# Generated by FakeRAM 2.0
VERSION 5.7 ;
BUSBITCHARS "[]" ;
PROPERTYDEFINITIONS
  MACRO width INTEGER ;
  MACRO depth INTEGER ;
  MACRO banks INTEGER ;
END PROPERTYDEFINITIONS
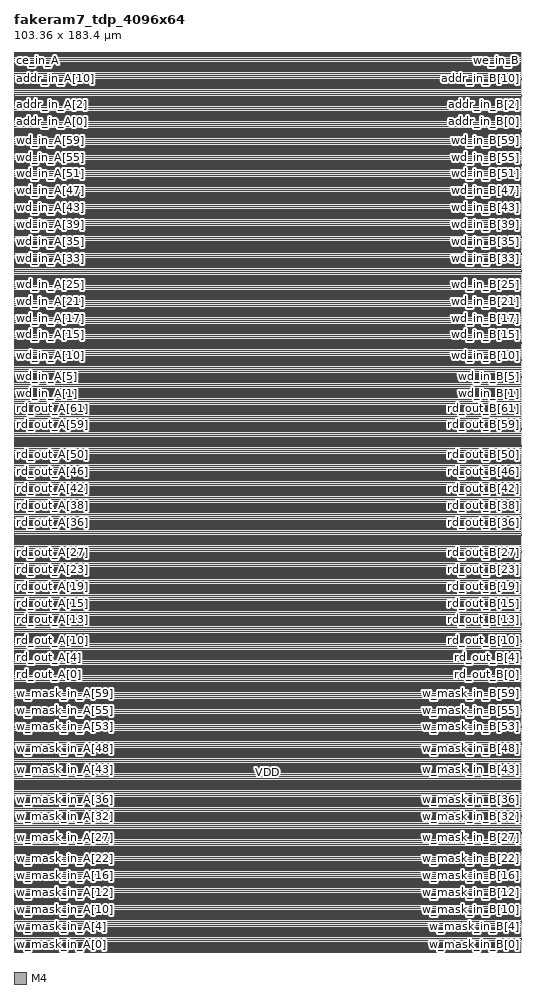
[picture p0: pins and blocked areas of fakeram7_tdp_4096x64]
MACRO fakeram7_tdp_4096x64
  PROPERTY width 64 ;
  PROPERTY depth 4096 ;
  PROPERTY banks 8 ;
  FOREIGN fakeram7_tdp_4096x64 0 0 ;
  SYMMETRY X Y ;
  SIZE 103.360 BY 183.400 ;
  CLASS BLOCK ;
  PIN w_mask_in_A[0]
    DIRECTION INPUT ;
    USE SIGNAL ;
    SHAPE ABUTMENT ;
    PORT
      LAYER M4 ;
      RECT 0.000 0.048 0.024 0.072 ;
    END
  END w_mask_in_A[0]
  PIN w_mask_in_B[0]
    DIRECTION INPUT ;
    USE SIGNAL ;
    SHAPE ABUTMENT ;
    PORT
      LAYER M4 ;
      RECT 103.336 0.048 103.360 0.072 ;
    END
  END w_mask_in_B[0]
  PIN w_mask_in_A[1]
    DIRECTION INPUT ;
    USE SIGNAL ;
    SHAPE ABUTMENT ;
    PORT
      LAYER M4 ;
      RECT 0.000 0.912 0.024 0.936 ;
    END
  END w_mask_in_A[1]
  PIN w_mask_in_B[1]
    DIRECTION INPUT ;
    USE SIGNAL ;
    SHAPE ABUTMENT ;
    PORT
      LAYER M4 ;
      RECT 103.336 0.912 103.360 0.936 ;
    END
  END w_mask_in_B[1]
  PIN w_mask_in_A[2]
    DIRECTION INPUT ;
    USE SIGNAL ;
    SHAPE ABUTMENT ;
    PORT
      LAYER M4 ;
      RECT 0.000 1.776 0.024 1.800 ;
    END
  END w_mask_in_A[2]
  PIN w_mask_in_B[2]
    DIRECTION INPUT ;
    USE SIGNAL ;
    SHAPE ABUTMENT ;
    PORT
      LAYER M4 ;
      RECT 103.336 1.776 103.360 1.800 ;
    END
  END w_mask_in_B[2]
  PIN w_mask_in_A[3]
    DIRECTION INPUT ;
    USE SIGNAL ;
    SHAPE ABUTMENT ;
    PORT
      LAYER M4 ;
      RECT 0.000 2.640 0.024 2.664 ;
    END
  END w_mask_in_A[3]
  PIN w_mask_in_B[3]
    DIRECTION INPUT ;
    USE SIGNAL ;
    SHAPE ABUTMENT ;
    PORT
      LAYER M4 ;
      RECT 103.336 2.640 103.360 2.664 ;
    END
  END w_mask_in_B[3]
  PIN w_mask_in_A[4]
    DIRECTION INPUT ;
    USE SIGNAL ;
    SHAPE ABUTMENT ;
    PORT
      LAYER M4 ;
      RECT 0.000 3.504 0.024 3.528 ;
    END
  END w_mask_in_A[4]
  PIN w_mask_in_B[4]
    DIRECTION INPUT ;
    USE SIGNAL ;
    SHAPE ABUTMENT ;
    PORT
      LAYER M4 ;
      RECT 103.336 3.504 103.360 3.528 ;
    END
  END w_mask_in_B[4]
  PIN w_mask_in_A[5]
    DIRECTION INPUT ;
    USE SIGNAL ;
    SHAPE ABUTMENT ;
    PORT
      LAYER M4 ;
      RECT 0.000 4.368 0.024 4.392 ;
    END
  END w_mask_in_A[5]
  PIN w_mask_in_B[5]
    DIRECTION INPUT ;
    USE SIGNAL ;
    SHAPE ABUTMENT ;
    PORT
      LAYER M4 ;
      RECT 103.336 4.368 103.360 4.392 ;
    END
  END w_mask_in_B[5]
  PIN w_mask_in_A[6]
    DIRECTION INPUT ;
    USE SIGNAL ;
    SHAPE ABUTMENT ;
    PORT
      LAYER M4 ;
      RECT 0.000 5.232 0.024 5.256 ;
    END
  END w_mask_in_A[6]
  PIN w_mask_in_B[6]
    DIRECTION INPUT ;
    USE SIGNAL ;
    SHAPE ABUTMENT ;
    PORT
      LAYER M4 ;
      RECT 103.336 5.232 103.360 5.256 ;
    END
  END w_mask_in_B[6]
  PIN w_mask_in_A[7]
    DIRECTION INPUT ;
    USE SIGNAL ;
    SHAPE ABUTMENT ;
    PORT
      LAYER M4 ;
      RECT 0.000 6.096 0.024 6.120 ;
    END
  END w_mask_in_A[7]
  PIN w_mask_in_B[7]
    DIRECTION INPUT ;
    USE SIGNAL ;
    SHAPE ABUTMENT ;
    PORT
      LAYER M4 ;
      RECT 103.336 6.096 103.360 6.120 ;
    END
  END w_mask_in_B[7]
  PIN w_mask_in_A[8]
    DIRECTION INPUT ;
    USE SIGNAL ;
    SHAPE ABUTMENT ;
    PORT
      LAYER M4 ;
      RECT 0.000 6.960 0.024 6.984 ;
    END
  END w_mask_in_A[8]
  PIN w_mask_in_B[8]
    DIRECTION INPUT ;
    USE SIGNAL ;
    SHAPE ABUTMENT ;
    PORT
      LAYER M4 ;
      RECT 103.336 6.960 103.360 6.984 ;
    END
  END w_mask_in_B[8]
  PIN w_mask_in_A[9]
    DIRECTION INPUT ;
    USE SIGNAL ;
    SHAPE ABUTMENT ;
    PORT
      LAYER M4 ;
      RECT 0.000 7.824 0.024 7.848 ;
    END
  END w_mask_in_A[9]
  PIN w_mask_in_B[9]
    DIRECTION INPUT ;
    USE SIGNAL ;
    SHAPE ABUTMENT ;
    PORT
      LAYER M4 ;
      RECT 103.336 7.824 103.360 7.848 ;
    END
  END w_mask_in_B[9]
  PIN w_mask_in_A[10]
    DIRECTION INPUT ;
    USE SIGNAL ;
    SHAPE ABUTMENT ;
    PORT
      LAYER M4 ;
      RECT 0.000 8.688 0.024 8.712 ;
    END
  END w_mask_in_A[10]
  PIN w_mask_in_B[10]
    DIRECTION INPUT ;
    USE SIGNAL ;
    SHAPE ABUTMENT ;
    PORT
      LAYER M4 ;
      RECT 103.336 8.688 103.360 8.712 ;
    END
  END w_mask_in_B[10]
  PIN w_mask_in_A[11]
    DIRECTION INPUT ;
    USE SIGNAL ;
    SHAPE ABUTMENT ;
    PORT
      LAYER M4 ;
      RECT 0.000 9.552 0.024 9.576 ;
    END
  END w_mask_in_A[11]
  PIN w_mask_in_B[11]
    DIRECTION INPUT ;
    USE SIGNAL ;
    SHAPE ABUTMENT ;
    PORT
      LAYER M4 ;
      RECT 103.336 9.552 103.360 9.576 ;
    END
  END w_mask_in_B[11]
  PIN w_mask_in_A[12]
    DIRECTION INPUT ;
    USE SIGNAL ;
    SHAPE ABUTMENT ;
    PORT
      LAYER M4 ;
      RECT 0.000 10.416 0.024 10.440 ;
    END
  END w_mask_in_A[12]
  PIN w_mask_in_B[12]
    DIRECTION INPUT ;
    USE SIGNAL ;
    SHAPE ABUTMENT ;
    PORT
      LAYER M4 ;
      RECT 103.336 10.416 103.360 10.440 ;
    END
  END w_mask_in_B[12]
  PIN w_mask_in_A[13]
    DIRECTION INPUT ;
    USE SIGNAL ;
    SHAPE ABUTMENT ;
    PORT
      LAYER M4 ;
      RECT 0.000 11.280 0.024 11.304 ;
    END
  END w_mask_in_A[13]
  PIN w_mask_in_B[13]
    DIRECTION INPUT ;
    USE SIGNAL ;
    SHAPE ABUTMENT ;
    PORT
      LAYER M4 ;
      RECT 103.336 11.280 103.360 11.304 ;
    END
  END w_mask_in_B[13]
  PIN w_mask_in_A[14]
    DIRECTION INPUT ;
    USE SIGNAL ;
    SHAPE ABUTMENT ;
    PORT
      LAYER M4 ;
      RECT 0.000 12.144 0.024 12.168 ;
    END
  END w_mask_in_A[14]
  PIN w_mask_in_B[14]
    DIRECTION INPUT ;
    USE SIGNAL ;
    SHAPE ABUTMENT ;
    PORT
      LAYER M4 ;
      RECT 103.336 12.144 103.360 12.168 ;
    END
  END w_mask_in_B[14]
  PIN w_mask_in_A[15]
    DIRECTION INPUT ;
    USE SIGNAL ;
    SHAPE ABUTMENT ;
    PORT
      LAYER M4 ;
      RECT 0.000 13.008 0.024 13.032 ;
    END
  END w_mask_in_A[15]
  PIN w_mask_in_B[15]
    DIRECTION INPUT ;
    USE SIGNAL ;
    SHAPE ABUTMENT ;
    PORT
      LAYER M4 ;
      RECT 103.336 13.008 103.360 13.032 ;
    END
  END w_mask_in_B[15]
  PIN w_mask_in_A[16]
    DIRECTION INPUT ;
    USE SIGNAL ;
    SHAPE ABUTMENT ;
    PORT
      LAYER M4 ;
      RECT 0.000 13.872 0.024 13.896 ;
    END
  END w_mask_in_A[16]
  PIN w_mask_in_B[16]
    DIRECTION INPUT ;
    USE SIGNAL ;
    SHAPE ABUTMENT ;
    PORT
      LAYER M4 ;
      RECT 103.336 13.872 103.360 13.896 ;
    END
  END w_mask_in_B[16]
  PIN w_mask_in_A[17]
    DIRECTION INPUT ;
    USE SIGNAL ;
    SHAPE ABUTMENT ;
    PORT
      LAYER M4 ;
      RECT 0.000 14.736 0.024 14.760 ;
    END
  END w_mask_in_A[17]
  PIN w_mask_in_B[17]
    DIRECTION INPUT ;
    USE SIGNAL ;
    SHAPE ABUTMENT ;
    PORT
      LAYER M4 ;
      RECT 103.336 14.736 103.360 14.760 ;
    END
  END w_mask_in_B[17]
  PIN w_mask_in_A[18]
    DIRECTION INPUT ;
    USE SIGNAL ;
    SHAPE ABUTMENT ;
    PORT
      LAYER M4 ;
      RECT 0.000 15.600 0.024 15.624 ;
    END
  END w_mask_in_A[18]
  PIN w_mask_in_B[18]
    DIRECTION INPUT ;
    USE SIGNAL ;
    SHAPE ABUTMENT ;
    PORT
      LAYER M4 ;
      RECT 103.336 15.600 103.360 15.624 ;
    END
  END w_mask_in_B[18]
  PIN w_mask_in_A[19]
    DIRECTION INPUT ;
    USE SIGNAL ;
    SHAPE ABUTMENT ;
    PORT
      LAYER M4 ;
      RECT 0.000 16.464 0.024 16.488 ;
    END
  END w_mask_in_A[19]
  PIN w_mask_in_B[19]
    DIRECTION INPUT ;
    USE SIGNAL ;
    SHAPE ABUTMENT ;
    PORT
      LAYER M4 ;
      RECT 103.336 16.464 103.360 16.488 ;
    END
  END w_mask_in_B[19]
  PIN w_mask_in_A[20]
    DIRECTION INPUT ;
    USE SIGNAL ;
    SHAPE ABUTMENT ;
    PORT
      LAYER M4 ;
      RECT 0.000 17.328 0.024 17.352 ;
    END
  END w_mask_in_A[20]
  PIN w_mask_in_B[20]
    DIRECTION INPUT ;
    USE SIGNAL ;
    SHAPE ABUTMENT ;
    PORT
      LAYER M4 ;
      RECT 103.336 17.328 103.360 17.352 ;
    END
  END w_mask_in_B[20]
  PIN w_mask_in_A[21]
    DIRECTION INPUT ;
    USE SIGNAL ;
    SHAPE ABUTMENT ;
    PORT
      LAYER M4 ;
      RECT 0.000 18.192 0.024 18.216 ;
    END
  END w_mask_in_A[21]
  PIN w_mask_in_B[21]
    DIRECTION INPUT ;
    USE SIGNAL ;
    SHAPE ABUTMENT ;
    PORT
      LAYER M4 ;
      RECT 103.336 18.192 103.360 18.216 ;
    END
  END w_mask_in_B[21]
  PIN w_mask_in_A[22]
    DIRECTION INPUT ;
    USE SIGNAL ;
    SHAPE ABUTMENT ;
    PORT
      LAYER M4 ;
      RECT 0.000 19.056 0.024 19.080 ;
    END
  END w_mask_in_A[22]
  PIN w_mask_in_B[22]
    DIRECTION INPUT ;
    USE SIGNAL ;
    SHAPE ABUTMENT ;
    PORT
      LAYER M4 ;
      RECT 103.336 19.056 103.360 19.080 ;
    END
  END w_mask_in_B[22]
  PIN w_mask_in_A[23]
    DIRECTION INPUT ;
    USE SIGNAL ;
    SHAPE ABUTMENT ;
    PORT
      LAYER M4 ;
      RECT 0.000 19.920 0.024 19.944 ;
    END
  END w_mask_in_A[23]
  PIN w_mask_in_B[23]
    DIRECTION INPUT ;
    USE SIGNAL ;
    SHAPE ABUTMENT ;
    PORT
      LAYER M4 ;
      RECT 103.336 19.920 103.360 19.944 ;
    END
  END w_mask_in_B[23]
  PIN w_mask_in_A[24]
    DIRECTION INPUT ;
    USE SIGNAL ;
    SHAPE ABUTMENT ;
    PORT
      LAYER M4 ;
      RECT 0.000 20.784 0.024 20.808 ;
    END
  END w_mask_in_A[24]
  PIN w_mask_in_B[24]
    DIRECTION INPUT ;
    USE SIGNAL ;
    SHAPE ABUTMENT ;
    PORT
      LAYER M4 ;
      RECT 103.336 20.784 103.360 20.808 ;
    END
  END w_mask_in_B[24]
  PIN w_mask_in_A[25]
    DIRECTION INPUT ;
    USE SIGNAL ;
    SHAPE ABUTMENT ;
    PORT
      LAYER M4 ;
      RECT 0.000 21.648 0.024 21.672 ;
    END
  END w_mask_in_A[25]
  PIN w_mask_in_B[25]
    DIRECTION INPUT ;
    USE SIGNAL ;
    SHAPE ABUTMENT ;
    PORT
      LAYER M4 ;
      RECT 103.336 21.648 103.360 21.672 ;
    END
  END w_mask_in_B[25]
  PIN w_mask_in_A[26]
    DIRECTION INPUT ;
    USE SIGNAL ;
    SHAPE ABUTMENT ;
    PORT
      LAYER M4 ;
      RECT 0.000 22.512 0.024 22.536 ;
    END
  END w_mask_in_A[26]
  PIN w_mask_in_B[26]
    DIRECTION INPUT ;
    USE SIGNAL ;
    SHAPE ABUTMENT ;
    PORT
      LAYER M4 ;
      RECT 103.336 22.512 103.360 22.536 ;
    END
  END w_mask_in_B[26]
  PIN w_mask_in_A[27]
    DIRECTION INPUT ;
    USE SIGNAL ;
    SHAPE ABUTMENT ;
    PORT
      LAYER M4 ;
      RECT 0.000 23.376 0.024 23.400 ;
    END
  END w_mask_in_A[27]
  PIN w_mask_in_B[27]
    DIRECTION INPUT ;
    USE SIGNAL ;
    SHAPE ABUTMENT ;
    PORT
      LAYER M4 ;
      RECT 103.336 23.376 103.360 23.400 ;
    END
  END w_mask_in_B[27]
  PIN w_mask_in_A[28]
    DIRECTION INPUT ;
    USE SIGNAL ;
    SHAPE ABUTMENT ;
    PORT
      LAYER M4 ;
      RECT 0.000 24.240 0.024 24.264 ;
    END
  END w_mask_in_A[28]
  PIN w_mask_in_B[28]
    DIRECTION INPUT ;
    USE SIGNAL ;
    SHAPE ABUTMENT ;
    PORT
      LAYER M4 ;
      RECT 103.336 24.240 103.360 24.264 ;
    END
  END w_mask_in_B[28]
  PIN w_mask_in_A[29]
    DIRECTION INPUT ;
    USE SIGNAL ;
    SHAPE ABUTMENT ;
    PORT
      LAYER M4 ;
      RECT 0.000 25.104 0.024 25.128 ;
    END
  END w_mask_in_A[29]
  PIN w_mask_in_B[29]
    DIRECTION INPUT ;
    USE SIGNAL ;
    SHAPE ABUTMENT ;
    PORT
      LAYER M4 ;
      RECT 103.336 25.104 103.360 25.128 ;
    END
  END w_mask_in_B[29]
  PIN w_mask_in_A[30]
    DIRECTION INPUT ;
    USE SIGNAL ;
    SHAPE ABUTMENT ;
    PORT
      LAYER M4 ;
      RECT 0.000 25.968 0.024 25.992 ;
    END
  END w_mask_in_A[30]
  PIN w_mask_in_B[30]
    DIRECTION INPUT ;
    USE SIGNAL ;
    SHAPE ABUTMENT ;
    PORT
      LAYER M4 ;
      RECT 103.336 25.968 103.360 25.992 ;
    END
  END w_mask_in_B[30]
  PIN w_mask_in_A[31]
    DIRECTION INPUT ;
    USE SIGNAL ;
    SHAPE ABUTMENT ;
    PORT
      LAYER M4 ;
      RECT 0.000 26.832 0.024 26.856 ;
    END
  END w_mask_in_A[31]
  PIN w_mask_in_B[31]
    DIRECTION INPUT ;
    USE SIGNAL ;
    SHAPE ABUTMENT ;
    PORT
      LAYER M4 ;
      RECT 103.336 26.832 103.360 26.856 ;
    END
  END w_mask_in_B[31]
  PIN w_mask_in_A[32]
    DIRECTION INPUT ;
    USE SIGNAL ;
    SHAPE ABUTMENT ;
    PORT
      LAYER M4 ;
      RECT 0.000 27.696 0.024 27.720 ;
    END
  END w_mask_in_A[32]
  PIN w_mask_in_B[32]
    DIRECTION INPUT ;
    USE SIGNAL ;
    SHAPE ABUTMENT ;
    PORT
      LAYER M4 ;
      RECT 103.336 27.696 103.360 27.720 ;
    END
  END w_mask_in_B[32]
  PIN w_mask_in_A[33]
    DIRECTION INPUT ;
    USE SIGNAL ;
    SHAPE ABUTMENT ;
    PORT
      LAYER M4 ;
      RECT 0.000 28.560 0.024 28.584 ;
    END
  END w_mask_in_A[33]
  PIN w_mask_in_B[33]
    DIRECTION INPUT ;
    USE SIGNAL ;
    SHAPE ABUTMENT ;
    PORT
      LAYER M4 ;
      RECT 103.336 28.560 103.360 28.584 ;
    END
  END w_mask_in_B[33]
  PIN w_mask_in_A[34]
    DIRECTION INPUT ;
    USE SIGNAL ;
    SHAPE ABUTMENT ;
    PORT
      LAYER M4 ;
      RECT 0.000 29.424 0.024 29.448 ;
    END
  END w_mask_in_A[34]
  PIN w_mask_in_B[34]
    DIRECTION INPUT ;
    USE SIGNAL ;
    SHAPE ABUTMENT ;
    PORT
      LAYER M4 ;
      RECT 103.336 29.424 103.360 29.448 ;
    END
  END w_mask_in_B[34]
  PIN w_mask_in_A[35]
    DIRECTION INPUT ;
    USE SIGNAL ;
    SHAPE ABUTMENT ;
    PORT
      LAYER M4 ;
      RECT 0.000 30.288 0.024 30.312 ;
    END
  END w_mask_in_A[35]
  PIN w_mask_in_B[35]
    DIRECTION INPUT ;
    USE SIGNAL ;
    SHAPE ABUTMENT ;
    PORT
      LAYER M4 ;
      RECT 103.336 30.288 103.360 30.312 ;
    END
  END w_mask_in_B[35]
  PIN w_mask_in_A[36]
    DIRECTION INPUT ;
    USE SIGNAL ;
    SHAPE ABUTMENT ;
    PORT
      LAYER M4 ;
      RECT 0.000 31.152 0.024 31.176 ;
    END
  END w_mask_in_A[36]
  PIN w_mask_in_B[36]
    DIRECTION INPUT ;
    USE SIGNAL ;
    SHAPE ABUTMENT ;
    PORT
      LAYER M4 ;
      RECT 103.336 31.152 103.360 31.176 ;
    END
  END w_mask_in_B[36]
  PIN w_mask_in_A[37]
    DIRECTION INPUT ;
    USE SIGNAL ;
    SHAPE ABUTMENT ;
    PORT
      LAYER M4 ;
      RECT 0.000 32.016 0.024 32.040 ;
    END
  END w_mask_in_A[37]
  PIN w_mask_in_B[37]
    DIRECTION INPUT ;
    USE SIGNAL ;
    SHAPE ABUTMENT ;
    PORT
      LAYER M4 ;
      RECT 103.336 32.016 103.360 32.040 ;
    END
  END w_mask_in_B[37]
  PIN w_mask_in_A[38]
    DIRECTION INPUT ;
    USE SIGNAL ;
    SHAPE ABUTMENT ;
    PORT
      LAYER M4 ;
      RECT 0.000 32.880 0.024 32.904 ;
    END
  END w_mask_in_A[38]
  PIN w_mask_in_B[38]
    DIRECTION INPUT ;
    USE SIGNAL ;
    SHAPE ABUTMENT ;
    PORT
      LAYER M4 ;
      RECT 103.336 32.880 103.360 32.904 ;
    END
  END w_mask_in_B[38]
  PIN w_mask_in_A[39]
    DIRECTION INPUT ;
    USE SIGNAL ;
    SHAPE ABUTMENT ;
    PORT
      LAYER M4 ;
      RECT 0.000 33.744 0.024 33.768 ;
    END
  END w_mask_in_A[39]
  PIN w_mask_in_B[39]
    DIRECTION INPUT ;
    USE SIGNAL ;
    SHAPE ABUTMENT ;
    PORT
      LAYER M4 ;
      RECT 103.336 33.744 103.360 33.768 ;
    END
  END w_mask_in_B[39]
  PIN w_mask_in_A[40]
    DIRECTION INPUT ;
    USE SIGNAL ;
    SHAPE ABUTMENT ;
    PORT
      LAYER M4 ;
      RECT 0.000 34.608 0.024 34.632 ;
    END
  END w_mask_in_A[40]
  PIN w_mask_in_B[40]
    DIRECTION INPUT ;
    USE SIGNAL ;
    SHAPE ABUTMENT ;
    PORT
      LAYER M4 ;
      RECT 103.336 34.608 103.360 34.632 ;
    END
  END w_mask_in_B[40]
  PIN w_mask_in_A[41]
    DIRECTION INPUT ;
    USE SIGNAL ;
    SHAPE ABUTMENT ;
    PORT
      LAYER M4 ;
      RECT 0.000 35.472 0.024 35.496 ;
    END
  END w_mask_in_A[41]
  PIN w_mask_in_B[41]
    DIRECTION INPUT ;
    USE SIGNAL ;
    SHAPE ABUTMENT ;
    PORT
      LAYER M4 ;
      RECT 103.336 35.472 103.360 35.496 ;
    END
  END w_mask_in_B[41]
  PIN w_mask_in_A[42]
    DIRECTION INPUT ;
    USE SIGNAL ;
    SHAPE ABUTMENT ;
    PORT
      LAYER M4 ;
      RECT 0.000 36.336 0.024 36.360 ;
    END
  END w_mask_in_A[42]
  PIN w_mask_in_B[42]
    DIRECTION INPUT ;
    USE SIGNAL ;
    SHAPE ABUTMENT ;
    PORT
      LAYER M4 ;
      RECT 103.336 36.336 103.360 36.360 ;
    END
  END w_mask_in_B[42]
  PIN w_mask_in_A[43]
    DIRECTION INPUT ;
    USE SIGNAL ;
    SHAPE ABUTMENT ;
    PORT
      LAYER M4 ;
      RECT 0.000 37.200 0.024 37.224 ;
    END
  END w_mask_in_A[43]
  PIN w_mask_in_B[43]
    DIRECTION INPUT ;
    USE SIGNAL ;
    SHAPE ABUTMENT ;
    PORT
      LAYER M4 ;
      RECT 103.336 37.200 103.360 37.224 ;
    END
  END w_mask_in_B[43]
  PIN w_mask_in_A[44]
    DIRECTION INPUT ;
    USE SIGNAL ;
    SHAPE ABUTMENT ;
    PORT
      LAYER M4 ;
      RECT 0.000 38.064 0.024 38.088 ;
    END
  END w_mask_in_A[44]
  PIN w_mask_in_B[44]
    DIRECTION INPUT ;
    USE SIGNAL ;
    SHAPE ABUTMENT ;
    PORT
      LAYER M4 ;
      RECT 103.336 38.064 103.360 38.088 ;
    END
  END w_mask_in_B[44]
  PIN w_mask_in_A[45]
    DIRECTION INPUT ;
    USE SIGNAL ;
    SHAPE ABUTMENT ;
    PORT
      LAYER M4 ;
      RECT 0.000 38.928 0.024 38.952 ;
    END
  END w_mask_in_A[45]
  PIN w_mask_in_B[45]
    DIRECTION INPUT ;
    USE SIGNAL ;
    SHAPE ABUTMENT ;
    PORT
      LAYER M4 ;
      RECT 103.336 38.928 103.360 38.952 ;
    END
  END w_mask_in_B[45]
  PIN w_mask_in_A[46]
    DIRECTION INPUT ;
    USE SIGNAL ;
    SHAPE ABUTMENT ;
    PORT
      LAYER M4 ;
      RECT 0.000 39.792 0.024 39.816 ;
    END
  END w_mask_in_A[46]
  PIN w_mask_in_B[46]
    DIRECTION INPUT ;
    USE SIGNAL ;
    SHAPE ABUTMENT ;
    PORT
      LAYER M4 ;
      RECT 103.336 39.792 103.360 39.816 ;
    END
  END w_mask_in_B[46]
  PIN w_mask_in_A[47]
    DIRECTION INPUT ;
    USE SIGNAL ;
    SHAPE ABUTMENT ;
    PORT
      LAYER M4 ;
      RECT 0.000 40.656 0.024 40.680 ;
    END
  END w_mask_in_A[47]
  PIN w_mask_in_B[47]
    DIRECTION INPUT ;
    USE SIGNAL ;
    SHAPE ABUTMENT ;
    PORT
      LAYER M4 ;
      RECT 103.336 40.656 103.360 40.680 ;
    END
  END w_mask_in_B[47]
  PIN w_mask_in_A[48]
    DIRECTION INPUT ;
    USE SIGNAL ;
    SHAPE ABUTMENT ;
    PORT
      LAYER M4 ;
      RECT 0.000 41.520 0.024 41.544 ;
    END
  END w_mask_in_A[48]
  PIN w_mask_in_B[48]
    DIRECTION INPUT ;
    USE SIGNAL ;
    SHAPE ABUTMENT ;
    PORT
      LAYER M4 ;
      RECT 103.336 41.520 103.360 41.544 ;
    END
  END w_mask_in_B[48]
  PIN w_mask_in_A[49]
    DIRECTION INPUT ;
    USE SIGNAL ;
    SHAPE ABUTMENT ;
    PORT
      LAYER M4 ;
      RECT 0.000 42.384 0.024 42.408 ;
    END
  END w_mask_in_A[49]
  PIN w_mask_in_B[49]
    DIRECTION INPUT ;
    USE SIGNAL ;
    SHAPE ABUTMENT ;
    PORT
      LAYER M4 ;
      RECT 103.336 42.384 103.360 42.408 ;
    END
  END w_mask_in_B[49]
  PIN w_mask_in_A[50]
    DIRECTION INPUT ;
    USE SIGNAL ;
    SHAPE ABUTMENT ;
    PORT
      LAYER M4 ;
      RECT 0.000 43.248 0.024 43.272 ;
    END
  END w_mask_in_A[50]
  PIN w_mask_in_B[50]
    DIRECTION INPUT ;
    USE SIGNAL ;
    SHAPE ABUTMENT ;
    PORT
      LAYER M4 ;
      RECT 103.336 43.248 103.360 43.272 ;
    END
  END w_mask_in_B[50]
  PIN w_mask_in_A[51]
    DIRECTION INPUT ;
    USE SIGNAL ;
    SHAPE ABUTMENT ;
    PORT
      LAYER M4 ;
      RECT 0.000 44.112 0.024 44.136 ;
    END
  END w_mask_in_A[51]
  PIN w_mask_in_B[51]
    DIRECTION INPUT ;
    USE SIGNAL ;
    SHAPE ABUTMENT ;
    PORT
      LAYER M4 ;
      RECT 103.336 44.112 103.360 44.136 ;
    END
  END w_mask_in_B[51]
  PIN w_mask_in_A[52]
    DIRECTION INPUT ;
    USE SIGNAL ;
    SHAPE ABUTMENT ;
    PORT
      LAYER M4 ;
      RECT 0.000 44.976 0.024 45.000 ;
    END
  END w_mask_in_A[52]
  PIN w_mask_in_B[52]
    DIRECTION INPUT ;
    USE SIGNAL ;
    SHAPE ABUTMENT ;
    PORT
      LAYER M4 ;
      RECT 103.336 44.976 103.360 45.000 ;
    END
  END w_mask_in_B[52]
  PIN w_mask_in_A[53]
    DIRECTION INPUT ;
    USE SIGNAL ;
    SHAPE ABUTMENT ;
    PORT
      LAYER M4 ;
      RECT 0.000 45.840 0.024 45.864 ;
    END
  END w_mask_in_A[53]
  PIN w_mask_in_B[53]
    DIRECTION INPUT ;
    USE SIGNAL ;
    SHAPE ABUTMENT ;
    PORT
      LAYER M4 ;
      RECT 103.336 45.840 103.360 45.864 ;
    END
  END w_mask_in_B[53]
  PIN w_mask_in_A[54]
    DIRECTION INPUT ;
    USE SIGNAL ;
    SHAPE ABUTMENT ;
    PORT
      LAYER M4 ;
      RECT 0.000 46.704 0.024 46.728 ;
    END
  END w_mask_in_A[54]
  PIN w_mask_in_B[54]
    DIRECTION INPUT ;
    USE SIGNAL ;
    SHAPE ABUTMENT ;
    PORT
      LAYER M4 ;
      RECT 103.336 46.704 103.360 46.728 ;
    END
  END w_mask_in_B[54]
  PIN w_mask_in_A[55]
    DIRECTION INPUT ;
    USE SIGNAL ;
    SHAPE ABUTMENT ;
    PORT
      LAYER M4 ;
      RECT 0.000 47.568 0.024 47.592 ;
    END
  END w_mask_in_A[55]
  PIN w_mask_in_B[55]
    DIRECTION INPUT ;
    USE SIGNAL ;
    SHAPE ABUTMENT ;
    PORT
      LAYER M4 ;
      RECT 103.336 47.568 103.360 47.592 ;
    END
  END w_mask_in_B[55]
  PIN w_mask_in_A[56]
    DIRECTION INPUT ;
    USE SIGNAL ;
    SHAPE ABUTMENT ;
    PORT
      LAYER M4 ;
      RECT 0.000 48.432 0.024 48.456 ;
    END
  END w_mask_in_A[56]
  PIN w_mask_in_B[56]
    DIRECTION INPUT ;
    USE SIGNAL ;
    SHAPE ABUTMENT ;
    PORT
      LAYER M4 ;
      RECT 103.336 48.432 103.360 48.456 ;
    END
  END w_mask_in_B[56]
  PIN w_mask_in_A[57]
    DIRECTION INPUT ;
    USE SIGNAL ;
    SHAPE ABUTMENT ;
    PORT
      LAYER M4 ;
      RECT 0.000 49.296 0.024 49.320 ;
    END
  END w_mask_in_A[57]
  PIN w_mask_in_B[57]
    DIRECTION INPUT ;
    USE SIGNAL ;
    SHAPE ABUTMENT ;
    PORT
      LAYER M4 ;
      RECT 103.336 49.296 103.360 49.320 ;
    END
  END w_mask_in_B[57]
  PIN w_mask_in_A[58]
    DIRECTION INPUT ;
    USE SIGNAL ;
    SHAPE ABUTMENT ;
    PORT
      LAYER M4 ;
      RECT 0.000 50.160 0.024 50.184 ;
    END
  END w_mask_in_A[58]
  PIN w_mask_in_B[58]
    DIRECTION INPUT ;
    USE SIGNAL ;
    SHAPE ABUTMENT ;
    PORT
      LAYER M4 ;
      RECT 103.336 50.160 103.360 50.184 ;
    END
  END w_mask_in_B[58]
  PIN w_mask_in_A[59]
    DIRECTION INPUT ;
    USE SIGNAL ;
    SHAPE ABUTMENT ;
    PORT
      LAYER M4 ;
      RECT 0.000 51.024 0.024 51.048 ;
    END
  END w_mask_in_A[59]
  PIN w_mask_in_B[59]
    DIRECTION INPUT ;
    USE SIGNAL ;
    SHAPE ABUTMENT ;
    PORT
      LAYER M4 ;
      RECT 103.336 51.024 103.360 51.048 ;
    END
  END w_mask_in_B[59]
  PIN w_mask_in_A[60]
    DIRECTION INPUT ;
    USE SIGNAL ;
    SHAPE ABUTMENT ;
    PORT
      LAYER M4 ;
      RECT 0.000 51.888 0.024 51.912 ;
    END
  END w_mask_in_A[60]
  PIN w_mask_in_B[60]
    DIRECTION INPUT ;
    USE SIGNAL ;
    SHAPE ABUTMENT ;
    PORT
      LAYER M4 ;
      RECT 103.336 51.888 103.360 51.912 ;
    END
  END w_mask_in_B[60]
  PIN w_mask_in_A[61]
    DIRECTION INPUT ;
    USE SIGNAL ;
    SHAPE ABUTMENT ;
    PORT
      LAYER M4 ;
      RECT 0.000 52.752 0.024 52.776 ;
    END
  END w_mask_in_A[61]
  PIN w_mask_in_B[61]
    DIRECTION INPUT ;
    USE SIGNAL ;
    SHAPE ABUTMENT ;
    PORT
      LAYER M4 ;
      RECT 103.336 52.752 103.360 52.776 ;
    END
  END w_mask_in_B[61]
  PIN w_mask_in_A[62]
    DIRECTION INPUT ;
    USE SIGNAL ;
    SHAPE ABUTMENT ;
    PORT
      LAYER M4 ;
      RECT 0.000 53.616 0.024 53.640 ;
    END
  END w_mask_in_A[62]
  PIN w_mask_in_B[62]
    DIRECTION INPUT ;
    USE SIGNAL ;
    SHAPE ABUTMENT ;
    PORT
      LAYER M4 ;
      RECT 103.336 53.616 103.360 53.640 ;
    END
  END w_mask_in_B[62]
  PIN w_mask_in_A[63]
    DIRECTION INPUT ;
    USE SIGNAL ;
    SHAPE ABUTMENT ;
    PORT
      LAYER M4 ;
      RECT 0.000 54.480 0.024 54.504 ;
    END
  END w_mask_in_A[63]
  PIN w_mask_in_B[63]
    DIRECTION INPUT ;
    USE SIGNAL ;
    SHAPE ABUTMENT ;
    PORT
      LAYER M4 ;
      RECT 103.336 54.480 103.360 54.504 ;
    END
  END w_mask_in_B[63]
  PIN rd_out_A[0]
    DIRECTION OUTPUT ;
    USE SIGNAL ;
    SHAPE ABUTMENT ;
    PORT
      LAYER M4 ;
      RECT 0.000 56.448 0.024 56.472 ;
    END
  END rd_out_A[0]
  PIN rd_out_B[0]
    DIRECTION OUTPUT ;
    USE SIGNAL ;
    SHAPE ABUTMENT ;
    PORT
      LAYER M4 ;
      RECT 103.336 56.448 103.360 56.472 ;
    END
  END rd_out_B[0]
  PIN rd_out_A[1]
    DIRECTION OUTPUT ;
    USE SIGNAL ;
    SHAPE ABUTMENT ;
    PORT
      LAYER M4 ;
      RECT 0.000 57.312 0.024 57.336 ;
    END
  END rd_out_A[1]
  PIN rd_out_B[1]
    DIRECTION OUTPUT ;
    USE SIGNAL ;
    SHAPE ABUTMENT ;
    PORT
      LAYER M4 ;
      RECT 103.336 57.312 103.360 57.336 ;
    END
  END rd_out_B[1]
  PIN rd_out_A[2]
    DIRECTION OUTPUT ;
    USE SIGNAL ;
    SHAPE ABUTMENT ;
    PORT
      LAYER M4 ;
      RECT 0.000 58.176 0.024 58.200 ;
    END
  END rd_out_A[2]
  PIN rd_out_B[2]
    DIRECTION OUTPUT ;
    USE SIGNAL ;
    SHAPE ABUTMENT ;
    PORT
      LAYER M4 ;
      RECT 103.336 58.176 103.360 58.200 ;
    END
  END rd_out_B[2]
  PIN rd_out_A[3]
    DIRECTION OUTPUT ;
    USE SIGNAL ;
    SHAPE ABUTMENT ;
    PORT
      LAYER M4 ;
      RECT 0.000 59.040 0.024 59.064 ;
    END
  END rd_out_A[3]
  PIN rd_out_B[3]
    DIRECTION OUTPUT ;
    USE SIGNAL ;
    SHAPE ABUTMENT ;
    PORT
      LAYER M4 ;
      RECT 103.336 59.040 103.360 59.064 ;
    END
  END rd_out_B[3]
  PIN rd_out_A[4]
    DIRECTION OUTPUT ;
    USE SIGNAL ;
    SHAPE ABUTMENT ;
    PORT
      LAYER M4 ;
      RECT 0.000 59.904 0.024 59.928 ;
    END
  END rd_out_A[4]
  PIN rd_out_B[4]
    DIRECTION OUTPUT ;
    USE SIGNAL ;
    SHAPE ABUTMENT ;
    PORT
      LAYER M4 ;
      RECT 103.336 59.904 103.360 59.928 ;
    END
  END rd_out_B[4]
  PIN rd_out_A[5]
    DIRECTION OUTPUT ;
    USE SIGNAL ;
    SHAPE ABUTMENT ;
    PORT
      LAYER M4 ;
      RECT 0.000 60.768 0.024 60.792 ;
    END
  END rd_out_A[5]
  PIN rd_out_B[5]
    DIRECTION OUTPUT ;
    USE SIGNAL ;
    SHAPE ABUTMENT ;
    PORT
      LAYER M4 ;
      RECT 103.336 60.768 103.360 60.792 ;
    END
  END rd_out_B[5]
  PIN rd_out_A[6]
    DIRECTION OUTPUT ;
    USE SIGNAL ;
    SHAPE ABUTMENT ;
    PORT
      LAYER M4 ;
      RECT 0.000 61.632 0.024 61.656 ;
    END
  END rd_out_A[6]
  PIN rd_out_B[6]
    DIRECTION OUTPUT ;
    USE SIGNAL ;
    SHAPE ABUTMENT ;
    PORT
      LAYER M4 ;
      RECT 103.336 61.632 103.360 61.656 ;
    END
  END rd_out_B[6]
  PIN rd_out_A[7]
    DIRECTION OUTPUT ;
    USE SIGNAL ;
    SHAPE ABUTMENT ;
    PORT
      LAYER M4 ;
      RECT 0.000 62.496 0.024 62.520 ;
    END
  END rd_out_A[7]
  PIN rd_out_B[7]
    DIRECTION OUTPUT ;
    USE SIGNAL ;
    SHAPE ABUTMENT ;
    PORT
      LAYER M4 ;
      RECT 103.336 62.496 103.360 62.520 ;
    END
  END rd_out_B[7]
  PIN rd_out_A[8]
    DIRECTION OUTPUT ;
    USE SIGNAL ;
    SHAPE ABUTMENT ;
    PORT
      LAYER M4 ;
      RECT 0.000 63.360 0.024 63.384 ;
    END
  END rd_out_A[8]
  PIN rd_out_B[8]
    DIRECTION OUTPUT ;
    USE SIGNAL ;
    SHAPE ABUTMENT ;
    PORT
      LAYER M4 ;
      RECT 103.336 63.360 103.360 63.384 ;
    END
  END rd_out_B[8]
  PIN rd_out_A[9]
    DIRECTION OUTPUT ;
    USE SIGNAL ;
    SHAPE ABUTMENT ;
    PORT
      LAYER M4 ;
      RECT 0.000 64.224 0.024 64.248 ;
    END
  END rd_out_A[9]
  PIN rd_out_B[9]
    DIRECTION OUTPUT ;
    USE SIGNAL ;
    SHAPE ABUTMENT ;
    PORT
      LAYER M4 ;
      RECT 103.336 64.224 103.360 64.248 ;
    END
  END rd_out_B[9]
  PIN rd_out_A[10]
    DIRECTION OUTPUT ;
    USE SIGNAL ;
    SHAPE ABUTMENT ;
    PORT
      LAYER M4 ;
      RECT 0.000 65.088 0.024 65.112 ;
    END
  END rd_out_A[10]
  PIN rd_out_B[10]
    DIRECTION OUTPUT ;
    USE SIGNAL ;
    SHAPE ABUTMENT ;
    PORT
      LAYER M4 ;
      RECT 103.336 65.088 103.360 65.112 ;
    END
  END rd_out_B[10]
  PIN rd_out_A[11]
    DIRECTION OUTPUT ;
    USE SIGNAL ;
    SHAPE ABUTMENT ;
    PORT
      LAYER M4 ;
      RECT 0.000 65.952 0.024 65.976 ;
    END
  END rd_out_A[11]
  PIN rd_out_B[11]
    DIRECTION OUTPUT ;
    USE SIGNAL ;
    SHAPE ABUTMENT ;
    PORT
      LAYER M4 ;
      RECT 103.336 65.952 103.360 65.976 ;
    END
  END rd_out_B[11]
  PIN rd_out_A[12]
    DIRECTION OUTPUT ;
    USE SIGNAL ;
    SHAPE ABUTMENT ;
    PORT
      LAYER M4 ;
      RECT 0.000 66.816 0.024 66.840 ;
    END
  END rd_out_A[12]
  PIN rd_out_B[12]
    DIRECTION OUTPUT ;
    USE SIGNAL ;
    SHAPE ABUTMENT ;
    PORT
      LAYER M4 ;
      RECT 103.336 66.816 103.360 66.840 ;
    END
  END rd_out_B[12]
  PIN rd_out_A[13]
    DIRECTION OUTPUT ;
    USE SIGNAL ;
    SHAPE ABUTMENT ;
    PORT
      LAYER M4 ;
      RECT 0.000 67.680 0.024 67.704 ;
    END
  END rd_out_A[13]
  PIN rd_out_B[13]
    DIRECTION OUTPUT ;
    USE SIGNAL ;
    SHAPE ABUTMENT ;
    PORT
      LAYER M4 ;
      RECT 103.336 67.680 103.360 67.704 ;
    END
  END rd_out_B[13]
  PIN rd_out_A[14]
    DIRECTION OUTPUT ;
    USE SIGNAL ;
    SHAPE ABUTMENT ;
    PORT
      LAYER M4 ;
      RECT 0.000 68.544 0.024 68.568 ;
    END
  END rd_out_A[14]
  PIN rd_out_B[14]
    DIRECTION OUTPUT ;
    USE SIGNAL ;
    SHAPE ABUTMENT ;
    PORT
      LAYER M4 ;
      RECT 103.336 68.544 103.360 68.568 ;
    END
  END rd_out_B[14]
  PIN rd_out_A[15]
    DIRECTION OUTPUT ;
    USE SIGNAL ;
    SHAPE ABUTMENT ;
    PORT
      LAYER M4 ;
      RECT 0.000 69.408 0.024 69.432 ;
    END
  END rd_out_A[15]
  PIN rd_out_B[15]
    DIRECTION OUTPUT ;
    USE SIGNAL ;
    SHAPE ABUTMENT ;
    PORT
      LAYER M4 ;
      RECT 103.336 69.408 103.360 69.432 ;
    END
  END rd_out_B[15]
  PIN rd_out_A[16]
    DIRECTION OUTPUT ;
    USE SIGNAL ;
    SHAPE ABUTMENT ;
    PORT
      LAYER M4 ;
      RECT 0.000 70.272 0.024 70.296 ;
    END
  END rd_out_A[16]
  PIN rd_out_B[16]
    DIRECTION OUTPUT ;
    USE SIGNAL ;
    SHAPE ABUTMENT ;
    PORT
      LAYER M4 ;
      RECT 103.336 70.272 103.360 70.296 ;
    END
  END rd_out_B[16]
  PIN rd_out_A[17]
    DIRECTION OUTPUT ;
    USE SIGNAL ;
    SHAPE ABUTMENT ;
    PORT
      LAYER M4 ;
      RECT 0.000 71.136 0.024 71.160 ;
    END
  END rd_out_A[17]
  PIN rd_out_B[17]
    DIRECTION OUTPUT ;
    USE SIGNAL ;
    SHAPE ABUTMENT ;
    PORT
      LAYER M4 ;
      RECT 103.336 71.136 103.360 71.160 ;
    END
  END rd_out_B[17]
  PIN rd_out_A[18]
    DIRECTION OUTPUT ;
    USE SIGNAL ;
    SHAPE ABUTMENT ;
    PORT
      LAYER M4 ;
      RECT 0.000 72.000 0.024 72.024 ;
    END
  END rd_out_A[18]
  PIN rd_out_B[18]
    DIRECTION OUTPUT ;
    USE SIGNAL ;
    SHAPE ABUTMENT ;
    PORT
      LAYER M4 ;
      RECT 103.336 72.000 103.360 72.024 ;
    END
  END rd_out_B[18]
  PIN rd_out_A[19]
    DIRECTION OUTPUT ;
    USE SIGNAL ;
    SHAPE ABUTMENT ;
    PORT
      LAYER M4 ;
      RECT 0.000 72.864 0.024 72.888 ;
    END
  END rd_out_A[19]
  PIN rd_out_B[19]
    DIRECTION OUTPUT ;
    USE SIGNAL ;
    SHAPE ABUTMENT ;
    PORT
      LAYER M4 ;
      RECT 103.336 72.864 103.360 72.888 ;
    END
  END rd_out_B[19]
  PIN rd_out_A[20]
    DIRECTION OUTPUT ;
    USE SIGNAL ;
    SHAPE ABUTMENT ;
    PORT
      LAYER M4 ;
      RECT 0.000 73.728 0.024 73.752 ;
    END
  END rd_out_A[20]
  PIN rd_out_B[20]
    DIRECTION OUTPUT ;
    USE SIGNAL ;
    SHAPE ABUTMENT ;
    PORT
      LAYER M4 ;
      RECT 103.336 73.728 103.360 73.752 ;
    END
  END rd_out_B[20]
  PIN rd_out_A[21]
    DIRECTION OUTPUT ;
    USE SIGNAL ;
    SHAPE ABUTMENT ;
    PORT
      LAYER M4 ;
      RECT 0.000 74.592 0.024 74.616 ;
    END
  END rd_out_A[21]
  PIN rd_out_B[21]
    DIRECTION OUTPUT ;
    USE SIGNAL ;
    SHAPE ABUTMENT ;
    PORT
      LAYER M4 ;
      RECT 103.336 74.592 103.360 74.616 ;
    END
  END rd_out_B[21]
  PIN rd_out_A[22]
    DIRECTION OUTPUT ;
    USE SIGNAL ;
    SHAPE ABUTMENT ;
    PORT
      LAYER M4 ;
      RECT 0.000 75.456 0.024 75.480 ;
    END
  END rd_out_A[22]
  PIN rd_out_B[22]
    DIRECTION OUTPUT ;
    USE SIGNAL ;
    SHAPE ABUTMENT ;
    PORT
      LAYER M4 ;
      RECT 103.336 75.456 103.360 75.480 ;
    END
  END rd_out_B[22]
  PIN rd_out_A[23]
    DIRECTION OUTPUT ;
    USE SIGNAL ;
    SHAPE ABUTMENT ;
    PORT
      LAYER M4 ;
      RECT 0.000 76.320 0.024 76.344 ;
    END
  END rd_out_A[23]
  PIN rd_out_B[23]
    DIRECTION OUTPUT ;
    USE SIGNAL ;
    SHAPE ABUTMENT ;
    PORT
      LAYER M4 ;
      RECT 103.336 76.320 103.360 76.344 ;
    END
  END rd_out_B[23]
  PIN rd_out_A[24]
    DIRECTION OUTPUT ;
    USE SIGNAL ;
    SHAPE ABUTMENT ;
    PORT
      LAYER M4 ;
      RECT 0.000 77.184 0.024 77.208 ;
    END
  END rd_out_A[24]
  PIN rd_out_B[24]
    DIRECTION OUTPUT ;
    USE SIGNAL ;
    SHAPE ABUTMENT ;
    PORT
      LAYER M4 ;
      RECT 103.336 77.184 103.360 77.208 ;
    END
  END rd_out_B[24]
  PIN rd_out_A[25]
    DIRECTION OUTPUT ;
    USE SIGNAL ;
    SHAPE ABUTMENT ;
    PORT
      LAYER M4 ;
      RECT 0.000 78.048 0.024 78.072 ;
    END
  END rd_out_A[25]
  PIN rd_out_B[25]
    DIRECTION OUTPUT ;
    USE SIGNAL ;
    SHAPE ABUTMENT ;
    PORT
      LAYER M4 ;
      RECT 103.336 78.048 103.360 78.072 ;
    END
  END rd_out_B[25]
  PIN rd_out_A[26]
    DIRECTION OUTPUT ;
    USE SIGNAL ;
    SHAPE ABUTMENT ;
    PORT
      LAYER M4 ;
      RECT 0.000 78.912 0.024 78.936 ;
    END
  END rd_out_A[26]
  PIN rd_out_B[26]
    DIRECTION OUTPUT ;
    USE SIGNAL ;
    SHAPE ABUTMENT ;
    PORT
      LAYER M4 ;
      RECT 103.336 78.912 103.360 78.936 ;
    END
  END rd_out_B[26]
  PIN rd_out_A[27]
    DIRECTION OUTPUT ;
    USE SIGNAL ;
    SHAPE ABUTMENT ;
    PORT
      LAYER M4 ;
      RECT 0.000 79.776 0.024 79.800 ;
    END
  END rd_out_A[27]
  PIN rd_out_B[27]
    DIRECTION OUTPUT ;
    USE SIGNAL ;
    SHAPE ABUTMENT ;
    PORT
      LAYER M4 ;
      RECT 103.336 79.776 103.360 79.800 ;
    END
  END rd_out_B[27]
  PIN rd_out_A[28]
    DIRECTION OUTPUT ;
    USE SIGNAL ;
    SHAPE ABUTMENT ;
    PORT
      LAYER M4 ;
      RECT 0.000 80.640 0.024 80.664 ;
    END
  END rd_out_A[28]
  PIN rd_out_B[28]
    DIRECTION OUTPUT ;
    USE SIGNAL ;
    SHAPE ABUTMENT ;
    PORT
      LAYER M4 ;
      RECT 103.336 80.640 103.360 80.664 ;
    END
  END rd_out_B[28]
  PIN rd_out_A[29]
    DIRECTION OUTPUT ;
    USE SIGNAL ;
    SHAPE ABUTMENT ;
    PORT
      LAYER M4 ;
      RECT 0.000 81.504 0.024 81.528 ;
    END
  END rd_out_A[29]
  PIN rd_out_B[29]
    DIRECTION OUTPUT ;
    USE SIGNAL ;
    SHAPE ABUTMENT ;
    PORT
      LAYER M4 ;
      RECT 103.336 81.504 103.360 81.528 ;
    END
  END rd_out_B[29]
  PIN rd_out_A[30]
    DIRECTION OUTPUT ;
    USE SIGNAL ;
    SHAPE ABUTMENT ;
    PORT
      LAYER M4 ;
      RECT 0.000 82.368 0.024 82.392 ;
    END
  END rd_out_A[30]
  PIN rd_out_B[30]
    DIRECTION OUTPUT ;
    USE SIGNAL ;
    SHAPE ABUTMENT ;
    PORT
      LAYER M4 ;
      RECT 103.336 82.368 103.360 82.392 ;
    END
  END rd_out_B[30]
  PIN rd_out_A[31]
    DIRECTION OUTPUT ;
    USE SIGNAL ;
    SHAPE ABUTMENT ;
    PORT
      LAYER M4 ;
      RECT 0.000 83.232 0.024 83.256 ;
    END
  END rd_out_A[31]
  PIN rd_out_B[31]
    DIRECTION OUTPUT ;
    USE SIGNAL ;
    SHAPE ABUTMENT ;
    PORT
      LAYER M4 ;
      RECT 103.336 83.232 103.360 83.256 ;
    END
  END rd_out_B[31]
  PIN rd_out_A[32]
    DIRECTION OUTPUT ;
    USE SIGNAL ;
    SHAPE ABUTMENT ;
    PORT
      LAYER M4 ;
      RECT 0.000 84.096 0.024 84.120 ;
    END
  END rd_out_A[32]
  PIN rd_out_B[32]
    DIRECTION OUTPUT ;
    USE SIGNAL ;
    SHAPE ABUTMENT ;
    PORT
      LAYER M4 ;
      RECT 103.336 84.096 103.360 84.120 ;
    END
  END rd_out_B[32]
  PIN rd_out_A[33]
    DIRECTION OUTPUT ;
    USE SIGNAL ;
    SHAPE ABUTMENT ;
    PORT
      LAYER M4 ;
      RECT 0.000 84.960 0.024 84.984 ;
    END
  END rd_out_A[33]
  PIN rd_out_B[33]
    DIRECTION OUTPUT ;
    USE SIGNAL ;
    SHAPE ABUTMENT ;
    PORT
      LAYER M4 ;
      RECT 103.336 84.960 103.360 84.984 ;
    END
  END rd_out_B[33]
  PIN rd_out_A[34]
    DIRECTION OUTPUT ;
    USE SIGNAL ;
    SHAPE ABUTMENT ;
    PORT
      LAYER M4 ;
      RECT 0.000 85.824 0.024 85.848 ;
    END
  END rd_out_A[34]
  PIN rd_out_B[34]
    DIRECTION OUTPUT ;
    USE SIGNAL ;
    SHAPE ABUTMENT ;
    PORT
      LAYER M4 ;
      RECT 103.336 85.824 103.360 85.848 ;
    END
  END rd_out_B[34]
  PIN rd_out_A[35]
    DIRECTION OUTPUT ;
    USE SIGNAL ;
    SHAPE ABUTMENT ;
    PORT
      LAYER M4 ;
      RECT 0.000 86.688 0.024 86.712 ;
    END
  END rd_out_A[35]
  PIN rd_out_B[35]
    DIRECTION OUTPUT ;
    USE SIGNAL ;
    SHAPE ABUTMENT ;
    PORT
      LAYER M4 ;
      RECT 103.336 86.688 103.360 86.712 ;
    END
  END rd_out_B[35]
  PIN rd_out_A[36]
    DIRECTION OUTPUT ;
    USE SIGNAL ;
    SHAPE ABUTMENT ;
    PORT
      LAYER M4 ;
      RECT 0.000 87.552 0.024 87.576 ;
    END
  END rd_out_A[36]
  PIN rd_out_B[36]
    DIRECTION OUTPUT ;
    USE SIGNAL ;
    SHAPE ABUTMENT ;
    PORT
      LAYER M4 ;
      RECT 103.336 87.552 103.360 87.576 ;
    END
  END rd_out_B[36]
  PIN rd_out_A[37]
    DIRECTION OUTPUT ;
    USE SIGNAL ;
    SHAPE ABUTMENT ;
    PORT
      LAYER M4 ;
      RECT 0.000 88.416 0.024 88.440 ;
    END
  END rd_out_A[37]
  PIN rd_out_B[37]
    DIRECTION OUTPUT ;
    USE SIGNAL ;
    SHAPE ABUTMENT ;
    PORT
      LAYER M4 ;
      RECT 103.336 88.416 103.360 88.440 ;
    END
  END rd_out_B[37]
  PIN rd_out_A[38]
    DIRECTION OUTPUT ;
    USE SIGNAL ;
    SHAPE ABUTMENT ;
    PORT
      LAYER M4 ;
      RECT 0.000 89.280 0.024 89.304 ;
    END
  END rd_out_A[38]
  PIN rd_out_B[38]
    DIRECTION OUTPUT ;
    USE SIGNAL ;
    SHAPE ABUTMENT ;
    PORT
      LAYER M4 ;
      RECT 103.336 89.280 103.360 89.304 ;
    END
  END rd_out_B[38]
  PIN rd_out_A[39]
    DIRECTION OUTPUT ;
    USE SIGNAL ;
    SHAPE ABUTMENT ;
    PORT
      LAYER M4 ;
      RECT 0.000 90.144 0.024 90.168 ;
    END
  END rd_out_A[39]
  PIN rd_out_B[39]
    DIRECTION OUTPUT ;
    USE SIGNAL ;
    SHAPE ABUTMENT ;
    PORT
      LAYER M4 ;
      RECT 103.336 90.144 103.360 90.168 ;
    END
  END rd_out_B[39]
  PIN rd_out_A[40]
    DIRECTION OUTPUT ;
    USE SIGNAL ;
    SHAPE ABUTMENT ;
    PORT
      LAYER M4 ;
      RECT 0.000 91.008 0.024 91.032 ;
    END
  END rd_out_A[40]
  PIN rd_out_B[40]
    DIRECTION OUTPUT ;
    USE SIGNAL ;
    SHAPE ABUTMENT ;
    PORT
      LAYER M4 ;
      RECT 103.336 91.008 103.360 91.032 ;
    END
  END rd_out_B[40]
  PIN rd_out_A[41]
    DIRECTION OUTPUT ;
    USE SIGNAL ;
    SHAPE ABUTMENT ;
    PORT
      LAYER M4 ;
      RECT 0.000 91.872 0.024 91.896 ;
    END
  END rd_out_A[41]
  PIN rd_out_B[41]
    DIRECTION OUTPUT ;
    USE SIGNAL ;
    SHAPE ABUTMENT ;
    PORT
      LAYER M4 ;
      RECT 103.336 91.872 103.360 91.896 ;
    END
  END rd_out_B[41]
  PIN rd_out_A[42]
    DIRECTION OUTPUT ;
    USE SIGNAL ;
    SHAPE ABUTMENT ;
    PORT
      LAYER M4 ;
      RECT 0.000 92.736 0.024 92.760 ;
    END
  END rd_out_A[42]
  PIN rd_out_B[42]
    DIRECTION OUTPUT ;
    USE SIGNAL ;
    SHAPE ABUTMENT ;
    PORT
      LAYER M4 ;
      RECT 103.336 92.736 103.360 92.760 ;
    END
  END rd_out_B[42]
  PIN rd_out_A[43]
    DIRECTION OUTPUT ;
    USE SIGNAL ;
    SHAPE ABUTMENT ;
    PORT
      LAYER M4 ;
      RECT 0.000 93.600 0.024 93.624 ;
    END
  END rd_out_A[43]
  PIN rd_out_B[43]
    DIRECTION OUTPUT ;
    USE SIGNAL ;
    SHAPE ABUTMENT ;
    PORT
      LAYER M4 ;
      RECT 103.336 93.600 103.360 93.624 ;
    END
  END rd_out_B[43]
  PIN rd_out_A[44]
    DIRECTION OUTPUT ;
    USE SIGNAL ;
    SHAPE ABUTMENT ;
    PORT
      LAYER M4 ;
      RECT 0.000 94.464 0.024 94.488 ;
    END
  END rd_out_A[44]
  PIN rd_out_B[44]
    DIRECTION OUTPUT ;
    USE SIGNAL ;
    SHAPE ABUTMENT ;
    PORT
      LAYER M4 ;
      RECT 103.336 94.464 103.360 94.488 ;
    END
  END rd_out_B[44]
  PIN rd_out_A[45]
    DIRECTION OUTPUT ;
    USE SIGNAL ;
    SHAPE ABUTMENT ;
    PORT
      LAYER M4 ;
      RECT 0.000 95.328 0.024 95.352 ;
    END
  END rd_out_A[45]
  PIN rd_out_B[45]
    DIRECTION OUTPUT ;
    USE SIGNAL ;
    SHAPE ABUTMENT ;
    PORT
      LAYER M4 ;
      RECT 103.336 95.328 103.360 95.352 ;
    END
  END rd_out_B[45]
  PIN rd_out_A[46]
    DIRECTION OUTPUT ;
    USE SIGNAL ;
    SHAPE ABUTMENT ;
    PORT
      LAYER M4 ;
      RECT 0.000 96.192 0.024 96.216 ;
    END
  END rd_out_A[46]
  PIN rd_out_B[46]
    DIRECTION OUTPUT ;
    USE SIGNAL ;
    SHAPE ABUTMENT ;
    PORT
      LAYER M4 ;
      RECT 103.336 96.192 103.360 96.216 ;
    END
  END rd_out_B[46]
  PIN rd_out_A[47]
    DIRECTION OUTPUT ;
    USE SIGNAL ;
    SHAPE ABUTMENT ;
    PORT
      LAYER M4 ;
      RECT 0.000 97.056 0.024 97.080 ;
    END
  END rd_out_A[47]
  PIN rd_out_B[47]
    DIRECTION OUTPUT ;
    USE SIGNAL ;
    SHAPE ABUTMENT ;
    PORT
      LAYER M4 ;
      RECT 103.336 97.056 103.360 97.080 ;
    END
  END rd_out_B[47]
  PIN rd_out_A[48]
    DIRECTION OUTPUT ;
    USE SIGNAL ;
    SHAPE ABUTMENT ;
    PORT
      LAYER M4 ;
      RECT 0.000 97.920 0.024 97.944 ;
    END
  END rd_out_A[48]
  PIN rd_out_B[48]
    DIRECTION OUTPUT ;
    USE SIGNAL ;
    SHAPE ABUTMENT ;
    PORT
      LAYER M4 ;
      RECT 103.336 97.920 103.360 97.944 ;
    END
  END rd_out_B[48]
  PIN rd_out_A[49]
    DIRECTION OUTPUT ;
    USE SIGNAL ;
    SHAPE ABUTMENT ;
    PORT
      LAYER M4 ;
      RECT 0.000 98.784 0.024 98.808 ;
    END
  END rd_out_A[49]
  PIN rd_out_B[49]
    DIRECTION OUTPUT ;
    USE SIGNAL ;
    SHAPE ABUTMENT ;
    PORT
      LAYER M4 ;
      RECT 103.336 98.784 103.360 98.808 ;
    END
  END rd_out_B[49]
  PIN rd_out_A[50]
    DIRECTION OUTPUT ;
    USE SIGNAL ;
    SHAPE ABUTMENT ;
    PORT
      LAYER M4 ;
      RECT 0.000 99.648 0.024 99.672 ;
    END
  END rd_out_A[50]
  PIN rd_out_B[50]
    DIRECTION OUTPUT ;
    USE SIGNAL ;
    SHAPE ABUTMENT ;
    PORT
      LAYER M4 ;
      RECT 103.336 99.648 103.360 99.672 ;
    END
  END rd_out_B[50]
  PIN rd_out_A[51]
    DIRECTION OUTPUT ;
    USE SIGNAL ;
    SHAPE ABUTMENT ;
    PORT
      LAYER M4 ;
      RECT 0.000 100.512 0.024 100.536 ;
    END
  END rd_out_A[51]
  PIN rd_out_B[51]
    DIRECTION OUTPUT ;
    USE SIGNAL ;
    SHAPE ABUTMENT ;
    PORT
      LAYER M4 ;
      RECT 103.336 100.512 103.360 100.536 ;
    END
  END rd_out_B[51]
  PIN rd_out_A[52]
    DIRECTION OUTPUT ;
    USE SIGNAL ;
    SHAPE ABUTMENT ;
    PORT
      LAYER M4 ;
      RECT 0.000 101.376 0.024 101.400 ;
    END
  END rd_out_A[52]
  PIN rd_out_B[52]
    DIRECTION OUTPUT ;
    USE SIGNAL ;
    SHAPE ABUTMENT ;
    PORT
      LAYER M4 ;
      RECT 103.336 101.376 103.360 101.400 ;
    END
  END rd_out_B[52]
  PIN rd_out_A[53]
    DIRECTION OUTPUT ;
    USE SIGNAL ;
    SHAPE ABUTMENT ;
    PORT
      LAYER M4 ;
      RECT 0.000 102.240 0.024 102.264 ;
    END
  END rd_out_A[53]
  PIN rd_out_B[53]
    DIRECTION OUTPUT ;
    USE SIGNAL ;
    SHAPE ABUTMENT ;
    PORT
      LAYER M4 ;
      RECT 103.336 102.240 103.360 102.264 ;
    END
  END rd_out_B[53]
  PIN rd_out_A[54]
    DIRECTION OUTPUT ;
    USE SIGNAL ;
    SHAPE ABUTMENT ;
    PORT
      LAYER M4 ;
      RECT 0.000 103.104 0.024 103.128 ;
    END
  END rd_out_A[54]
  PIN rd_out_B[54]
    DIRECTION OUTPUT ;
    USE SIGNAL ;
    SHAPE ABUTMENT ;
    PORT
      LAYER M4 ;
      RECT 103.336 103.104 103.360 103.128 ;
    END
  END rd_out_B[54]
  PIN rd_out_A[55]
    DIRECTION OUTPUT ;
    USE SIGNAL ;
    SHAPE ABUTMENT ;
    PORT
      LAYER M4 ;
      RECT 0.000 103.968 0.024 103.992 ;
    END
  END rd_out_A[55]
  PIN rd_out_B[55]
    DIRECTION OUTPUT ;
    USE SIGNAL ;
    SHAPE ABUTMENT ;
    PORT
      LAYER M4 ;
      RECT 103.336 103.968 103.360 103.992 ;
    END
  END rd_out_B[55]
  PIN rd_out_A[56]
    DIRECTION OUTPUT ;
    USE SIGNAL ;
    SHAPE ABUTMENT ;
    PORT
      LAYER M4 ;
      RECT 0.000 104.832 0.024 104.856 ;
    END
  END rd_out_A[56]
  PIN rd_out_B[56]
    DIRECTION OUTPUT ;
    USE SIGNAL ;
    SHAPE ABUTMENT ;
    PORT
      LAYER M4 ;
      RECT 103.336 104.832 103.360 104.856 ;
    END
  END rd_out_B[56]
  PIN rd_out_A[57]
    DIRECTION OUTPUT ;
    USE SIGNAL ;
    SHAPE ABUTMENT ;
    PORT
      LAYER M4 ;
      RECT 0.000 105.696 0.024 105.720 ;
    END
  END rd_out_A[57]
  PIN rd_out_B[57]
    DIRECTION OUTPUT ;
    USE SIGNAL ;
    SHAPE ABUTMENT ;
    PORT
      LAYER M4 ;
      RECT 103.336 105.696 103.360 105.720 ;
    END
  END rd_out_B[57]
  PIN rd_out_A[58]
    DIRECTION OUTPUT ;
    USE SIGNAL ;
    SHAPE ABUTMENT ;
    PORT
      LAYER M4 ;
      RECT 0.000 106.560 0.024 106.584 ;
    END
  END rd_out_A[58]
  PIN rd_out_B[58]
    DIRECTION OUTPUT ;
    USE SIGNAL ;
    SHAPE ABUTMENT ;
    PORT
      LAYER M4 ;
      RECT 103.336 106.560 103.360 106.584 ;
    END
  END rd_out_B[58]
  PIN rd_out_A[59]
    DIRECTION OUTPUT ;
    USE SIGNAL ;
    SHAPE ABUTMENT ;
    PORT
      LAYER M4 ;
      RECT 0.000 107.424 0.024 107.448 ;
    END
  END rd_out_A[59]
  PIN rd_out_B[59]
    DIRECTION OUTPUT ;
    USE SIGNAL ;
    SHAPE ABUTMENT ;
    PORT
      LAYER M4 ;
      RECT 103.336 107.424 103.360 107.448 ;
    END
  END rd_out_B[59]
  PIN rd_out_A[60]
    DIRECTION OUTPUT ;
    USE SIGNAL ;
    SHAPE ABUTMENT ;
    PORT
      LAYER M4 ;
      RECT 0.000 108.288 0.024 108.312 ;
    END
  END rd_out_A[60]
  PIN rd_out_B[60]
    DIRECTION OUTPUT ;
    USE SIGNAL ;
    SHAPE ABUTMENT ;
    PORT
      LAYER M4 ;
      RECT 103.336 108.288 103.360 108.312 ;
    END
  END rd_out_B[60]
  PIN rd_out_A[61]
    DIRECTION OUTPUT ;
    USE SIGNAL ;
    SHAPE ABUTMENT ;
    PORT
      LAYER M4 ;
      RECT 0.000 109.152 0.024 109.176 ;
    END
  END rd_out_A[61]
  PIN rd_out_B[61]
    DIRECTION OUTPUT ;
    USE SIGNAL ;
    SHAPE ABUTMENT ;
    PORT
      LAYER M4 ;
      RECT 103.336 109.152 103.360 109.176 ;
    END
  END rd_out_B[61]
  PIN rd_out_A[62]
    DIRECTION OUTPUT ;
    USE SIGNAL ;
    SHAPE ABUTMENT ;
    PORT
      LAYER M4 ;
      RECT 0.000 110.016 0.024 110.040 ;
    END
  END rd_out_A[62]
  PIN rd_out_B[62]
    DIRECTION OUTPUT ;
    USE SIGNAL ;
    SHAPE ABUTMENT ;
    PORT
      LAYER M4 ;
      RECT 103.336 110.016 103.360 110.040 ;
    END
  END rd_out_B[62]
  PIN rd_out_A[63]
    DIRECTION OUTPUT ;
    USE SIGNAL ;
    SHAPE ABUTMENT ;
    PORT
      LAYER M4 ;
      RECT 0.000 110.880 0.024 110.904 ;
    END
  END rd_out_A[63]
  PIN rd_out_B[63]
    DIRECTION OUTPUT ;
    USE SIGNAL ;
    SHAPE ABUTMENT ;
    PORT
      LAYER M4 ;
      RECT 103.336 110.880 103.360 110.904 ;
    END
  END rd_out_B[63]
  PIN wd_in_A[0]
    DIRECTION INPUT ;
    USE SIGNAL ;
    SHAPE ABUTMENT ;
    PORT
      LAYER M4 ;
      RECT 0.000 112.848 0.024 112.872 ;
    END
  END wd_in_A[0]
  PIN wd_in_B[0]
    DIRECTION INPUT ;
    USE SIGNAL ;
    SHAPE ABUTMENT ;
    PORT
      LAYER M4 ;
      RECT 103.336 112.848 103.360 112.872 ;
    END
  END wd_in_B[0]
  PIN wd_in_A[1]
    DIRECTION INPUT ;
    USE SIGNAL ;
    SHAPE ABUTMENT ;
    PORT
      LAYER M4 ;
      RECT 0.000 113.712 0.024 113.736 ;
    END
  END wd_in_A[1]
  PIN wd_in_B[1]
    DIRECTION INPUT ;
    USE SIGNAL ;
    SHAPE ABUTMENT ;
    PORT
      LAYER M4 ;
      RECT 103.336 113.712 103.360 113.736 ;
    END
  END wd_in_B[1]
  PIN wd_in_A[2]
    DIRECTION INPUT ;
    USE SIGNAL ;
    SHAPE ABUTMENT ;
    PORT
      LAYER M4 ;
      RECT 0.000 114.576 0.024 114.600 ;
    END
  END wd_in_A[2]
  PIN wd_in_B[2]
    DIRECTION INPUT ;
    USE SIGNAL ;
    SHAPE ABUTMENT ;
    PORT
      LAYER M4 ;
      RECT 103.336 114.576 103.360 114.600 ;
    END
  END wd_in_B[2]
  PIN wd_in_A[3]
    DIRECTION INPUT ;
    USE SIGNAL ;
    SHAPE ABUTMENT ;
    PORT
      LAYER M4 ;
      RECT 0.000 115.440 0.024 115.464 ;
    END
  END wd_in_A[3]
  PIN wd_in_B[3]
    DIRECTION INPUT ;
    USE SIGNAL ;
    SHAPE ABUTMENT ;
    PORT
      LAYER M4 ;
      RECT 103.336 115.440 103.360 115.464 ;
    END
  END wd_in_B[3]
  PIN wd_in_A[4]
    DIRECTION INPUT ;
    USE SIGNAL ;
    SHAPE ABUTMENT ;
    PORT
      LAYER M4 ;
      RECT 0.000 116.304 0.024 116.328 ;
    END
  END wd_in_A[4]
  PIN wd_in_B[4]
    DIRECTION INPUT ;
    USE SIGNAL ;
    SHAPE ABUTMENT ;
    PORT
      LAYER M4 ;
      RECT 103.336 116.304 103.360 116.328 ;
    END
  END wd_in_B[4]
  PIN wd_in_A[5]
    DIRECTION INPUT ;
    USE SIGNAL ;
    SHAPE ABUTMENT ;
    PORT
      LAYER M4 ;
      RECT 0.000 117.168 0.024 117.192 ;
    END
  END wd_in_A[5]
  PIN wd_in_B[5]
    DIRECTION INPUT ;
    USE SIGNAL ;
    SHAPE ABUTMENT ;
    PORT
      LAYER M4 ;
      RECT 103.336 117.168 103.360 117.192 ;
    END
  END wd_in_B[5]
  PIN wd_in_A[6]
    DIRECTION INPUT ;
    USE SIGNAL ;
    SHAPE ABUTMENT ;
    PORT
      LAYER M4 ;
      RECT 0.000 118.032 0.024 118.056 ;
    END
  END wd_in_A[6]
  PIN wd_in_B[6]
    DIRECTION INPUT ;
    USE SIGNAL ;
    SHAPE ABUTMENT ;
    PORT
      LAYER M4 ;
      RECT 103.336 118.032 103.360 118.056 ;
    END
  END wd_in_B[6]
  PIN wd_in_A[7]
    DIRECTION INPUT ;
    USE SIGNAL ;
    SHAPE ABUTMENT ;
    PORT
      LAYER M4 ;
      RECT 0.000 118.896 0.024 118.920 ;
    END
  END wd_in_A[7]
  PIN wd_in_B[7]
    DIRECTION INPUT ;
    USE SIGNAL ;
    SHAPE ABUTMENT ;
    PORT
      LAYER M4 ;
      RECT 103.336 118.896 103.360 118.920 ;
    END
  END wd_in_B[7]
  PIN wd_in_A[8]
    DIRECTION INPUT ;
    USE SIGNAL ;
    SHAPE ABUTMENT ;
    PORT
      LAYER M4 ;
      RECT 0.000 119.760 0.024 119.784 ;
    END
  END wd_in_A[8]
  PIN wd_in_B[8]
    DIRECTION INPUT ;
    USE SIGNAL ;
    SHAPE ABUTMENT ;
    PORT
      LAYER M4 ;
      RECT 103.336 119.760 103.360 119.784 ;
    END
  END wd_in_B[8]
  PIN wd_in_A[9]
    DIRECTION INPUT ;
    USE SIGNAL ;
    SHAPE ABUTMENT ;
    PORT
      LAYER M4 ;
      RECT 0.000 120.624 0.024 120.648 ;
    END
  END wd_in_A[9]
  PIN wd_in_B[9]
    DIRECTION INPUT ;
    USE SIGNAL ;
    SHAPE ABUTMENT ;
    PORT
      LAYER M4 ;
      RECT 103.336 120.624 103.360 120.648 ;
    END
  END wd_in_B[9]
  PIN wd_in_A[10]
    DIRECTION INPUT ;
    USE SIGNAL ;
    SHAPE ABUTMENT ;
    PORT
      LAYER M4 ;
      RECT 0.000 121.488 0.024 121.512 ;
    END
  END wd_in_A[10]
  PIN wd_in_B[10]
    DIRECTION INPUT ;
    USE SIGNAL ;
    SHAPE ABUTMENT ;
    PORT
      LAYER M4 ;
      RECT 103.336 121.488 103.360 121.512 ;
    END
  END wd_in_B[10]
  PIN wd_in_A[11]
    DIRECTION INPUT ;
    USE SIGNAL ;
    SHAPE ABUTMENT ;
    PORT
      LAYER M4 ;
      RECT 0.000 122.352 0.024 122.376 ;
    END
  END wd_in_A[11]
  PIN wd_in_B[11]
    DIRECTION INPUT ;
    USE SIGNAL ;
    SHAPE ABUTMENT ;
    PORT
      LAYER M4 ;
      RECT 103.336 122.352 103.360 122.376 ;
    END
  END wd_in_B[11]
  PIN wd_in_A[12]
    DIRECTION INPUT ;
    USE SIGNAL ;
    SHAPE ABUTMENT ;
    PORT
      LAYER M4 ;
      RECT 0.000 123.216 0.024 123.240 ;
    END
  END wd_in_A[12]
  PIN wd_in_B[12]
    DIRECTION INPUT ;
    USE SIGNAL ;
    SHAPE ABUTMENT ;
    PORT
      LAYER M4 ;
      RECT 103.336 123.216 103.360 123.240 ;
    END
  END wd_in_B[12]
  PIN wd_in_A[13]
    DIRECTION INPUT ;
    USE SIGNAL ;
    SHAPE ABUTMENT ;
    PORT
      LAYER M4 ;
      RECT 0.000 124.080 0.024 124.104 ;
    END
  END wd_in_A[13]
  PIN wd_in_B[13]
    DIRECTION INPUT ;
    USE SIGNAL ;
    SHAPE ABUTMENT ;
    PORT
      LAYER M4 ;
      RECT 103.336 124.080 103.360 124.104 ;
    END
  END wd_in_B[13]
  PIN wd_in_A[14]
    DIRECTION INPUT ;
    USE SIGNAL ;
    SHAPE ABUTMENT ;
    PORT
      LAYER M4 ;
      RECT 0.000 124.944 0.024 124.968 ;
    END
  END wd_in_A[14]
  PIN wd_in_B[14]
    DIRECTION INPUT ;
    USE SIGNAL ;
    SHAPE ABUTMENT ;
    PORT
      LAYER M4 ;
      RECT 103.336 124.944 103.360 124.968 ;
    END
  END wd_in_B[14]
  PIN wd_in_A[15]
    DIRECTION INPUT ;
    USE SIGNAL ;
    SHAPE ABUTMENT ;
    PORT
      LAYER M4 ;
      RECT 0.000 125.808 0.024 125.832 ;
    END
  END wd_in_A[15]
  PIN wd_in_B[15]
    DIRECTION INPUT ;
    USE SIGNAL ;
    SHAPE ABUTMENT ;
    PORT
      LAYER M4 ;
      RECT 103.336 125.808 103.360 125.832 ;
    END
  END wd_in_B[15]
  PIN wd_in_A[16]
    DIRECTION INPUT ;
    USE SIGNAL ;
    SHAPE ABUTMENT ;
    PORT
      LAYER M4 ;
      RECT 0.000 126.672 0.024 126.696 ;
    END
  END wd_in_A[16]
  PIN wd_in_B[16]
    DIRECTION INPUT ;
    USE SIGNAL ;
    SHAPE ABUTMENT ;
    PORT
      LAYER M4 ;
      RECT 103.336 126.672 103.360 126.696 ;
    END
  END wd_in_B[16]
  PIN wd_in_A[17]
    DIRECTION INPUT ;
    USE SIGNAL ;
    SHAPE ABUTMENT ;
    PORT
      LAYER M4 ;
      RECT 0.000 127.536 0.024 127.560 ;
    END
  END wd_in_A[17]
  PIN wd_in_B[17]
    DIRECTION INPUT ;
    USE SIGNAL ;
    SHAPE ABUTMENT ;
    PORT
      LAYER M4 ;
      RECT 103.336 127.536 103.360 127.560 ;
    END
  END wd_in_B[17]
  PIN wd_in_A[18]
    DIRECTION INPUT ;
    USE SIGNAL ;
    SHAPE ABUTMENT ;
    PORT
      LAYER M4 ;
      RECT 0.000 128.400 0.024 128.424 ;
    END
  END wd_in_A[18]
  PIN wd_in_B[18]
    DIRECTION INPUT ;
    USE SIGNAL ;
    SHAPE ABUTMENT ;
    PORT
      LAYER M4 ;
      RECT 103.336 128.400 103.360 128.424 ;
    END
  END wd_in_B[18]
  PIN wd_in_A[19]
    DIRECTION INPUT ;
    USE SIGNAL ;
    SHAPE ABUTMENT ;
    PORT
      LAYER M4 ;
      RECT 0.000 129.264 0.024 129.288 ;
    END
  END wd_in_A[19]
  PIN wd_in_B[19]
    DIRECTION INPUT ;
    USE SIGNAL ;
    SHAPE ABUTMENT ;
    PORT
      LAYER M4 ;
      RECT 103.336 129.264 103.360 129.288 ;
    END
  END wd_in_B[19]
  PIN wd_in_A[20]
    DIRECTION INPUT ;
    USE SIGNAL ;
    SHAPE ABUTMENT ;
    PORT
      LAYER M4 ;
      RECT 0.000 130.128 0.024 130.152 ;
    END
  END wd_in_A[20]
  PIN wd_in_B[20]
    DIRECTION INPUT ;
    USE SIGNAL ;
    SHAPE ABUTMENT ;
    PORT
      LAYER M4 ;
      RECT 103.336 130.128 103.360 130.152 ;
    END
  END wd_in_B[20]
  PIN wd_in_A[21]
    DIRECTION INPUT ;
    USE SIGNAL ;
    SHAPE ABUTMENT ;
    PORT
      LAYER M4 ;
      RECT 0.000 130.992 0.024 131.016 ;
    END
  END wd_in_A[21]
  PIN wd_in_B[21]
    DIRECTION INPUT ;
    USE SIGNAL ;
    SHAPE ABUTMENT ;
    PORT
      LAYER M4 ;
      RECT 103.336 130.992 103.360 131.016 ;
    END
  END wd_in_B[21]
  PIN wd_in_A[22]
    DIRECTION INPUT ;
    USE SIGNAL ;
    SHAPE ABUTMENT ;
    PORT
      LAYER M4 ;
      RECT 0.000 131.856 0.024 131.880 ;
    END
  END wd_in_A[22]
  PIN wd_in_B[22]
    DIRECTION INPUT ;
    USE SIGNAL ;
    SHAPE ABUTMENT ;
    PORT
      LAYER M4 ;
      RECT 103.336 131.856 103.360 131.880 ;
    END
  END wd_in_B[22]
  PIN wd_in_A[23]
    DIRECTION INPUT ;
    USE SIGNAL ;
    SHAPE ABUTMENT ;
    PORT
      LAYER M4 ;
      RECT 0.000 132.720 0.024 132.744 ;
    END
  END wd_in_A[23]
  PIN wd_in_B[23]
    DIRECTION INPUT ;
    USE SIGNAL ;
    SHAPE ABUTMENT ;
    PORT
      LAYER M4 ;
      RECT 103.336 132.720 103.360 132.744 ;
    END
  END wd_in_B[23]
  PIN wd_in_A[24]
    DIRECTION INPUT ;
    USE SIGNAL ;
    SHAPE ABUTMENT ;
    PORT
      LAYER M4 ;
      RECT 0.000 133.584 0.024 133.608 ;
    END
  END wd_in_A[24]
  PIN wd_in_B[24]
    DIRECTION INPUT ;
    USE SIGNAL ;
    SHAPE ABUTMENT ;
    PORT
      LAYER M4 ;
      RECT 103.336 133.584 103.360 133.608 ;
    END
  END wd_in_B[24]
  PIN wd_in_A[25]
    DIRECTION INPUT ;
    USE SIGNAL ;
    SHAPE ABUTMENT ;
    PORT
      LAYER M4 ;
      RECT 0.000 134.448 0.024 134.472 ;
    END
  END wd_in_A[25]
  PIN wd_in_B[25]
    DIRECTION INPUT ;
    USE SIGNAL ;
    SHAPE ABUTMENT ;
    PORT
      LAYER M4 ;
      RECT 103.336 134.448 103.360 134.472 ;
    END
  END wd_in_B[25]
  PIN wd_in_A[26]
    DIRECTION INPUT ;
    USE SIGNAL ;
    SHAPE ABUTMENT ;
    PORT
      LAYER M4 ;
      RECT 0.000 135.312 0.024 135.336 ;
    END
  END wd_in_A[26]
  PIN wd_in_B[26]
    DIRECTION INPUT ;
    USE SIGNAL ;
    SHAPE ABUTMENT ;
    PORT
      LAYER M4 ;
      RECT 103.336 135.312 103.360 135.336 ;
    END
  END wd_in_B[26]
  PIN wd_in_A[27]
    DIRECTION INPUT ;
    USE SIGNAL ;
    SHAPE ABUTMENT ;
    PORT
      LAYER M4 ;
      RECT 0.000 136.176 0.024 136.200 ;
    END
  END wd_in_A[27]
  PIN wd_in_B[27]
    DIRECTION INPUT ;
    USE SIGNAL ;
    SHAPE ABUTMENT ;
    PORT
      LAYER M4 ;
      RECT 103.336 136.176 103.360 136.200 ;
    END
  END wd_in_B[27]
  PIN wd_in_A[28]
    DIRECTION INPUT ;
    USE SIGNAL ;
    SHAPE ABUTMENT ;
    PORT
      LAYER M4 ;
      RECT 0.000 137.040 0.024 137.064 ;
    END
  END wd_in_A[28]
  PIN wd_in_B[28]
    DIRECTION INPUT ;
    USE SIGNAL ;
    SHAPE ABUTMENT ;
    PORT
      LAYER M4 ;
      RECT 103.336 137.040 103.360 137.064 ;
    END
  END wd_in_B[28]
  PIN wd_in_A[29]
    DIRECTION INPUT ;
    USE SIGNAL ;
    SHAPE ABUTMENT ;
    PORT
      LAYER M4 ;
      RECT 0.000 137.904 0.024 137.928 ;
    END
  END wd_in_A[29]
  PIN wd_in_B[29]
    DIRECTION INPUT ;
    USE SIGNAL ;
    SHAPE ABUTMENT ;
    PORT
      LAYER M4 ;
      RECT 103.336 137.904 103.360 137.928 ;
    END
  END wd_in_B[29]
  PIN wd_in_A[30]
    DIRECTION INPUT ;
    USE SIGNAL ;
    SHAPE ABUTMENT ;
    PORT
      LAYER M4 ;
      RECT 0.000 138.768 0.024 138.792 ;
    END
  END wd_in_A[30]
  PIN wd_in_B[30]
    DIRECTION INPUT ;
    USE SIGNAL ;
    SHAPE ABUTMENT ;
    PORT
      LAYER M4 ;
      RECT 103.336 138.768 103.360 138.792 ;
    END
  END wd_in_B[30]
  PIN wd_in_A[31]
    DIRECTION INPUT ;
    USE SIGNAL ;
    SHAPE ABUTMENT ;
    PORT
      LAYER M4 ;
      RECT 0.000 139.632 0.024 139.656 ;
    END
  END wd_in_A[31]
  PIN wd_in_B[31]
    DIRECTION INPUT ;
    USE SIGNAL ;
    SHAPE ABUTMENT ;
    PORT
      LAYER M4 ;
      RECT 103.336 139.632 103.360 139.656 ;
    END
  END wd_in_B[31]
  PIN wd_in_A[32]
    DIRECTION INPUT ;
    USE SIGNAL ;
    SHAPE ABUTMENT ;
    PORT
      LAYER M4 ;
      RECT 0.000 140.496 0.024 140.520 ;
    END
  END wd_in_A[32]
  PIN wd_in_B[32]
    DIRECTION INPUT ;
    USE SIGNAL ;
    SHAPE ABUTMENT ;
    PORT
      LAYER M4 ;
      RECT 103.336 140.496 103.360 140.520 ;
    END
  END wd_in_B[32]
  PIN wd_in_A[33]
    DIRECTION INPUT ;
    USE SIGNAL ;
    SHAPE ABUTMENT ;
    PORT
      LAYER M4 ;
      RECT 0.000 141.360 0.024 141.384 ;
    END
  END wd_in_A[33]
  PIN wd_in_B[33]
    DIRECTION INPUT ;
    USE SIGNAL ;
    SHAPE ABUTMENT ;
    PORT
      LAYER M4 ;
      RECT 103.336 141.360 103.360 141.384 ;
    END
  END wd_in_B[33]
  PIN wd_in_A[34]
    DIRECTION INPUT ;
    USE SIGNAL ;
    SHAPE ABUTMENT ;
    PORT
      LAYER M4 ;
      RECT 0.000 142.224 0.024 142.248 ;
    END
  END wd_in_A[34]
  PIN wd_in_B[34]
    DIRECTION INPUT ;
    USE SIGNAL ;
    SHAPE ABUTMENT ;
    PORT
      LAYER M4 ;
      RECT 103.336 142.224 103.360 142.248 ;
    END
  END wd_in_B[34]
  PIN wd_in_A[35]
    DIRECTION INPUT ;
    USE SIGNAL ;
    SHAPE ABUTMENT ;
    PORT
      LAYER M4 ;
      RECT 0.000 143.088 0.024 143.112 ;
    END
  END wd_in_A[35]
  PIN wd_in_B[35]
    DIRECTION INPUT ;
    USE SIGNAL ;
    SHAPE ABUTMENT ;
    PORT
      LAYER M4 ;
      RECT 103.336 143.088 103.360 143.112 ;
    END
  END wd_in_B[35]
  PIN wd_in_A[36]
    DIRECTION INPUT ;
    USE SIGNAL ;
    SHAPE ABUTMENT ;
    PORT
      LAYER M4 ;
      RECT 0.000 143.952 0.024 143.976 ;
    END
  END wd_in_A[36]
  PIN wd_in_B[36]
    DIRECTION INPUT ;
    USE SIGNAL ;
    SHAPE ABUTMENT ;
    PORT
      LAYER M4 ;
      RECT 103.336 143.952 103.360 143.976 ;
    END
  END wd_in_B[36]
  PIN wd_in_A[37]
    DIRECTION INPUT ;
    USE SIGNAL ;
    SHAPE ABUTMENT ;
    PORT
      LAYER M4 ;
      RECT 0.000 144.816 0.024 144.840 ;
    END
  END wd_in_A[37]
  PIN wd_in_B[37]
    DIRECTION INPUT ;
    USE SIGNAL ;
    SHAPE ABUTMENT ;
    PORT
      LAYER M4 ;
      RECT 103.336 144.816 103.360 144.840 ;
    END
  END wd_in_B[37]
  PIN wd_in_A[38]
    DIRECTION INPUT ;
    USE SIGNAL ;
    SHAPE ABUTMENT ;
    PORT
      LAYER M4 ;
      RECT 0.000 145.680 0.024 145.704 ;
    END
  END wd_in_A[38]
  PIN wd_in_B[38]
    DIRECTION INPUT ;
    USE SIGNAL ;
    SHAPE ABUTMENT ;
    PORT
      LAYER M4 ;
      RECT 103.336 145.680 103.360 145.704 ;
    END
  END wd_in_B[38]
  PIN wd_in_A[39]
    DIRECTION INPUT ;
    USE SIGNAL ;
    SHAPE ABUTMENT ;
    PORT
      LAYER M4 ;
      RECT 0.000 146.544 0.024 146.568 ;
    END
  END wd_in_A[39]
  PIN wd_in_B[39]
    DIRECTION INPUT ;
    USE SIGNAL ;
    SHAPE ABUTMENT ;
    PORT
      LAYER M4 ;
      RECT 103.336 146.544 103.360 146.568 ;
    END
  END wd_in_B[39]
  PIN wd_in_A[40]
    DIRECTION INPUT ;
    USE SIGNAL ;
    SHAPE ABUTMENT ;
    PORT
      LAYER M4 ;
      RECT 0.000 147.408 0.024 147.432 ;
    END
  END wd_in_A[40]
  PIN wd_in_B[40]
    DIRECTION INPUT ;
    USE SIGNAL ;
    SHAPE ABUTMENT ;
    PORT
      LAYER M4 ;
      RECT 103.336 147.408 103.360 147.432 ;
    END
  END wd_in_B[40]
  PIN wd_in_A[41]
    DIRECTION INPUT ;
    USE SIGNAL ;
    SHAPE ABUTMENT ;
    PORT
      LAYER M4 ;
      RECT 0.000 148.272 0.024 148.296 ;
    END
  END wd_in_A[41]
  PIN wd_in_B[41]
    DIRECTION INPUT ;
    USE SIGNAL ;
    SHAPE ABUTMENT ;
    PORT
      LAYER M4 ;
      RECT 103.336 148.272 103.360 148.296 ;
    END
  END wd_in_B[41]
  PIN wd_in_A[42]
    DIRECTION INPUT ;
    USE SIGNAL ;
    SHAPE ABUTMENT ;
    PORT
      LAYER M4 ;
      RECT 0.000 149.136 0.024 149.160 ;
    END
  END wd_in_A[42]
  PIN wd_in_B[42]
    DIRECTION INPUT ;
    USE SIGNAL ;
    SHAPE ABUTMENT ;
    PORT
      LAYER M4 ;
      RECT 103.336 149.136 103.360 149.160 ;
    END
  END wd_in_B[42]
  PIN wd_in_A[43]
    DIRECTION INPUT ;
    USE SIGNAL ;
    SHAPE ABUTMENT ;
    PORT
      LAYER M4 ;
      RECT 0.000 150.000 0.024 150.024 ;
    END
  END wd_in_A[43]
  PIN wd_in_B[43]
    DIRECTION INPUT ;
    USE SIGNAL ;
    SHAPE ABUTMENT ;
    PORT
      LAYER M4 ;
      RECT 103.336 150.000 103.360 150.024 ;
    END
  END wd_in_B[43]
  PIN wd_in_A[44]
    DIRECTION INPUT ;
    USE SIGNAL ;
    SHAPE ABUTMENT ;
    PORT
      LAYER M4 ;
      RECT 0.000 150.864 0.024 150.888 ;
    END
  END wd_in_A[44]
  PIN wd_in_B[44]
    DIRECTION INPUT ;
    USE SIGNAL ;
    SHAPE ABUTMENT ;
    PORT
      LAYER M4 ;
      RECT 103.336 150.864 103.360 150.888 ;
    END
  END wd_in_B[44]
  PIN wd_in_A[45]
    DIRECTION INPUT ;
    USE SIGNAL ;
    SHAPE ABUTMENT ;
    PORT
      LAYER M4 ;
      RECT 0.000 151.728 0.024 151.752 ;
    END
  END wd_in_A[45]
  PIN wd_in_B[45]
    DIRECTION INPUT ;
    USE SIGNAL ;
    SHAPE ABUTMENT ;
    PORT
      LAYER M4 ;
      RECT 103.336 151.728 103.360 151.752 ;
    END
  END wd_in_B[45]
  PIN wd_in_A[46]
    DIRECTION INPUT ;
    USE SIGNAL ;
    SHAPE ABUTMENT ;
    PORT
      LAYER M4 ;
      RECT 0.000 152.592 0.024 152.616 ;
    END
  END wd_in_A[46]
  PIN wd_in_B[46]
    DIRECTION INPUT ;
    USE SIGNAL ;
    SHAPE ABUTMENT ;
    PORT
      LAYER M4 ;
      RECT 103.336 152.592 103.360 152.616 ;
    END
  END wd_in_B[46]
  PIN wd_in_A[47]
    DIRECTION INPUT ;
    USE SIGNAL ;
    SHAPE ABUTMENT ;
    PORT
      LAYER M4 ;
      RECT 0.000 153.456 0.024 153.480 ;
    END
  END wd_in_A[47]
  PIN wd_in_B[47]
    DIRECTION INPUT ;
    USE SIGNAL ;
    SHAPE ABUTMENT ;
    PORT
      LAYER M4 ;
      RECT 103.336 153.456 103.360 153.480 ;
    END
  END wd_in_B[47]
  PIN wd_in_A[48]
    DIRECTION INPUT ;
    USE SIGNAL ;
    SHAPE ABUTMENT ;
    PORT
      LAYER M4 ;
      RECT 0.000 154.320 0.024 154.344 ;
    END
  END wd_in_A[48]
  PIN wd_in_B[48]
    DIRECTION INPUT ;
    USE SIGNAL ;
    SHAPE ABUTMENT ;
    PORT
      LAYER M4 ;
      RECT 103.336 154.320 103.360 154.344 ;
    END
  END wd_in_B[48]
  PIN wd_in_A[49]
    DIRECTION INPUT ;
    USE SIGNAL ;
    SHAPE ABUTMENT ;
    PORT
      LAYER M4 ;
      RECT 0.000 155.184 0.024 155.208 ;
    END
  END wd_in_A[49]
  PIN wd_in_B[49]
    DIRECTION INPUT ;
    USE SIGNAL ;
    SHAPE ABUTMENT ;
    PORT
      LAYER M4 ;
      RECT 103.336 155.184 103.360 155.208 ;
    END
  END wd_in_B[49]
  PIN wd_in_A[50]
    DIRECTION INPUT ;
    USE SIGNAL ;
    SHAPE ABUTMENT ;
    PORT
      LAYER M4 ;
      RECT 0.000 156.048 0.024 156.072 ;
    END
  END wd_in_A[50]
  PIN wd_in_B[50]
    DIRECTION INPUT ;
    USE SIGNAL ;
    SHAPE ABUTMENT ;
    PORT
      LAYER M4 ;
      RECT 103.336 156.048 103.360 156.072 ;
    END
  END wd_in_B[50]
  PIN wd_in_A[51]
    DIRECTION INPUT ;
    USE SIGNAL ;
    SHAPE ABUTMENT ;
    PORT
      LAYER M4 ;
      RECT 0.000 156.912 0.024 156.936 ;
    END
  END wd_in_A[51]
  PIN wd_in_B[51]
    DIRECTION INPUT ;
    USE SIGNAL ;
    SHAPE ABUTMENT ;
    PORT
      LAYER M4 ;
      RECT 103.336 156.912 103.360 156.936 ;
    END
  END wd_in_B[51]
  PIN wd_in_A[52]
    DIRECTION INPUT ;
    USE SIGNAL ;
    SHAPE ABUTMENT ;
    PORT
      LAYER M4 ;
      RECT 0.000 157.776 0.024 157.800 ;
    END
  END wd_in_A[52]
  PIN wd_in_B[52]
    DIRECTION INPUT ;
    USE SIGNAL ;
    SHAPE ABUTMENT ;
    PORT
      LAYER M4 ;
      RECT 103.336 157.776 103.360 157.800 ;
    END
  END wd_in_B[52]
  PIN wd_in_A[53]
    DIRECTION INPUT ;
    USE SIGNAL ;
    SHAPE ABUTMENT ;
    PORT
      LAYER M4 ;
      RECT 0.000 158.640 0.024 158.664 ;
    END
  END wd_in_A[53]
  PIN wd_in_B[53]
    DIRECTION INPUT ;
    USE SIGNAL ;
    SHAPE ABUTMENT ;
    PORT
      LAYER M4 ;
      RECT 103.336 158.640 103.360 158.664 ;
    END
  END wd_in_B[53]
  PIN wd_in_A[54]
    DIRECTION INPUT ;
    USE SIGNAL ;
    SHAPE ABUTMENT ;
    PORT
      LAYER M4 ;
      RECT 0.000 159.504 0.024 159.528 ;
    END
  END wd_in_A[54]
  PIN wd_in_B[54]
    DIRECTION INPUT ;
    USE SIGNAL ;
    SHAPE ABUTMENT ;
    PORT
      LAYER M4 ;
      RECT 103.336 159.504 103.360 159.528 ;
    END
  END wd_in_B[54]
  PIN wd_in_A[55]
    DIRECTION INPUT ;
    USE SIGNAL ;
    SHAPE ABUTMENT ;
    PORT
      LAYER M4 ;
      RECT 0.000 160.368 0.024 160.392 ;
    END
  END wd_in_A[55]
  PIN wd_in_B[55]
    DIRECTION INPUT ;
    USE SIGNAL ;
    SHAPE ABUTMENT ;
    PORT
      LAYER M4 ;
      RECT 103.336 160.368 103.360 160.392 ;
    END
  END wd_in_B[55]
  PIN wd_in_A[56]
    DIRECTION INPUT ;
    USE SIGNAL ;
    SHAPE ABUTMENT ;
    PORT
      LAYER M4 ;
      RECT 0.000 161.232 0.024 161.256 ;
    END
  END wd_in_A[56]
  PIN wd_in_B[56]
    DIRECTION INPUT ;
    USE SIGNAL ;
    SHAPE ABUTMENT ;
    PORT
      LAYER M4 ;
      RECT 103.336 161.232 103.360 161.256 ;
    END
  END wd_in_B[56]
  PIN wd_in_A[57]
    DIRECTION INPUT ;
    USE SIGNAL ;
    SHAPE ABUTMENT ;
    PORT
      LAYER M4 ;
      RECT 0.000 162.096 0.024 162.120 ;
    END
  END wd_in_A[57]
  PIN wd_in_B[57]
    DIRECTION INPUT ;
    USE SIGNAL ;
    SHAPE ABUTMENT ;
    PORT
      LAYER M4 ;
      RECT 103.336 162.096 103.360 162.120 ;
    END
  END wd_in_B[57]
  PIN wd_in_A[58]
    DIRECTION INPUT ;
    USE SIGNAL ;
    SHAPE ABUTMENT ;
    PORT
      LAYER M4 ;
      RECT 0.000 162.960 0.024 162.984 ;
    END
  END wd_in_A[58]
  PIN wd_in_B[58]
    DIRECTION INPUT ;
    USE SIGNAL ;
    SHAPE ABUTMENT ;
    PORT
      LAYER M4 ;
      RECT 103.336 162.960 103.360 162.984 ;
    END
  END wd_in_B[58]
  PIN wd_in_A[59]
    DIRECTION INPUT ;
    USE SIGNAL ;
    SHAPE ABUTMENT ;
    PORT
      LAYER M4 ;
      RECT 0.000 163.824 0.024 163.848 ;
    END
  END wd_in_A[59]
  PIN wd_in_B[59]
    DIRECTION INPUT ;
    USE SIGNAL ;
    SHAPE ABUTMENT ;
    PORT
      LAYER M4 ;
      RECT 103.336 163.824 103.360 163.848 ;
    END
  END wd_in_B[59]
  PIN wd_in_A[60]
    DIRECTION INPUT ;
    USE SIGNAL ;
    SHAPE ABUTMENT ;
    PORT
      LAYER M4 ;
      RECT 0.000 164.688 0.024 164.712 ;
    END
  END wd_in_A[60]
  PIN wd_in_B[60]
    DIRECTION INPUT ;
    USE SIGNAL ;
    SHAPE ABUTMENT ;
    PORT
      LAYER M4 ;
      RECT 103.336 164.688 103.360 164.712 ;
    END
  END wd_in_B[60]
  PIN wd_in_A[61]
    DIRECTION INPUT ;
    USE SIGNAL ;
    SHAPE ABUTMENT ;
    PORT
      LAYER M4 ;
      RECT 0.000 165.552 0.024 165.576 ;
    END
  END wd_in_A[61]
  PIN wd_in_B[61]
    DIRECTION INPUT ;
    USE SIGNAL ;
    SHAPE ABUTMENT ;
    PORT
      LAYER M4 ;
      RECT 103.336 165.552 103.360 165.576 ;
    END
  END wd_in_B[61]
  PIN wd_in_A[62]
    DIRECTION INPUT ;
    USE SIGNAL ;
    SHAPE ABUTMENT ;
    PORT
      LAYER M4 ;
      RECT 0.000 166.416 0.024 166.440 ;
    END
  END wd_in_A[62]
  PIN wd_in_B[62]
    DIRECTION INPUT ;
    USE SIGNAL ;
    SHAPE ABUTMENT ;
    PORT
      LAYER M4 ;
      RECT 103.336 166.416 103.360 166.440 ;
    END
  END wd_in_B[62]
  PIN wd_in_A[63]
    DIRECTION INPUT ;
    USE SIGNAL ;
    SHAPE ABUTMENT ;
    PORT
      LAYER M4 ;
      RECT 0.000 167.280 0.024 167.304 ;
    END
  END wd_in_A[63]
  PIN wd_in_B[63]
    DIRECTION INPUT ;
    USE SIGNAL ;
    SHAPE ABUTMENT ;
    PORT
      LAYER M4 ;
      RECT 103.336 167.280 103.360 167.304 ;
    END
  END wd_in_B[63]
  PIN addr_in_A[0]
    DIRECTION INPUT ;
    USE SIGNAL ;
    SHAPE ABUTMENT ;
    PORT
      LAYER M4 ;
      RECT 0.000 169.248 0.024 169.272 ;
    END
  END addr_in_A[0]
  PIN addr_in_B[0]
    DIRECTION INPUT ;
    USE SIGNAL ;
    SHAPE ABUTMENT ;
    PORT
      LAYER M4 ;
      RECT 103.336 169.248 103.360 169.272 ;
    END
  END addr_in_B[0]
  PIN addr_in_A[1]
    DIRECTION INPUT ;
    USE SIGNAL ;
    SHAPE ABUTMENT ;
    PORT
      LAYER M4 ;
      RECT 0.000 170.112 0.024 170.136 ;
    END
  END addr_in_A[1]
  PIN addr_in_B[1]
    DIRECTION INPUT ;
    USE SIGNAL ;
    SHAPE ABUTMENT ;
    PORT
      LAYER M4 ;
      RECT 103.336 170.112 103.360 170.136 ;
    END
  END addr_in_B[1]
  PIN addr_in_A[2]
    DIRECTION INPUT ;
    USE SIGNAL ;
    SHAPE ABUTMENT ;
    PORT
      LAYER M4 ;
      RECT 0.000 170.976 0.024 171.000 ;
    END
  END addr_in_A[2]
  PIN addr_in_B[2]
    DIRECTION INPUT ;
    USE SIGNAL ;
    SHAPE ABUTMENT ;
    PORT
      LAYER M4 ;
      RECT 103.336 170.976 103.360 171.000 ;
    END
  END addr_in_B[2]
  PIN addr_in_A[3]
    DIRECTION INPUT ;
    USE SIGNAL ;
    SHAPE ABUTMENT ;
    PORT
      LAYER M4 ;
      RECT 0.000 171.840 0.024 171.864 ;
    END
  END addr_in_A[3]
  PIN addr_in_B[3]
    DIRECTION INPUT ;
    USE SIGNAL ;
    SHAPE ABUTMENT ;
    PORT
      LAYER M4 ;
      RECT 103.336 171.840 103.360 171.864 ;
    END
  END addr_in_B[3]
  PIN addr_in_A[4]
    DIRECTION INPUT ;
    USE SIGNAL ;
    SHAPE ABUTMENT ;
    PORT
      LAYER M4 ;
      RECT 0.000 172.704 0.024 172.728 ;
    END
  END addr_in_A[4]
  PIN addr_in_B[4]
    DIRECTION INPUT ;
    USE SIGNAL ;
    SHAPE ABUTMENT ;
    PORT
      LAYER M4 ;
      RECT 103.336 172.704 103.360 172.728 ;
    END
  END addr_in_B[4]
  PIN addr_in_A[5]
    DIRECTION INPUT ;
    USE SIGNAL ;
    SHAPE ABUTMENT ;
    PORT
      LAYER M4 ;
      RECT 0.000 173.568 0.024 173.592 ;
    END
  END addr_in_A[5]
  PIN addr_in_B[5]
    DIRECTION INPUT ;
    USE SIGNAL ;
    SHAPE ABUTMENT ;
    PORT
      LAYER M4 ;
      RECT 103.336 173.568 103.360 173.592 ;
    END
  END addr_in_B[5]
  PIN addr_in_A[6]
    DIRECTION INPUT ;
    USE SIGNAL ;
    SHAPE ABUTMENT ;
    PORT
      LAYER M4 ;
      RECT 0.000 174.432 0.024 174.456 ;
    END
  END addr_in_A[6]
  PIN addr_in_B[6]
    DIRECTION INPUT ;
    USE SIGNAL ;
    SHAPE ABUTMENT ;
    PORT
      LAYER M4 ;
      RECT 103.336 174.432 103.360 174.456 ;
    END
  END addr_in_B[6]
  PIN addr_in_A[7]
    DIRECTION INPUT ;
    USE SIGNAL ;
    SHAPE ABUTMENT ;
    PORT
      LAYER M4 ;
      RECT 0.000 175.296 0.024 175.320 ;
    END
  END addr_in_A[7]
  PIN addr_in_B[7]
    DIRECTION INPUT ;
    USE SIGNAL ;
    SHAPE ABUTMENT ;
    PORT
      LAYER M4 ;
      RECT 103.336 175.296 103.360 175.320 ;
    END
  END addr_in_B[7]
  PIN addr_in_A[8]
    DIRECTION INPUT ;
    USE SIGNAL ;
    SHAPE ABUTMENT ;
    PORT
      LAYER M4 ;
      RECT 0.000 176.160 0.024 176.184 ;
    END
  END addr_in_A[8]
  PIN addr_in_B[8]
    DIRECTION INPUT ;
    USE SIGNAL ;
    SHAPE ABUTMENT ;
    PORT
      LAYER M4 ;
      RECT 103.336 176.160 103.360 176.184 ;
    END
  END addr_in_B[8]
  PIN addr_in_A[9]
    DIRECTION INPUT ;
    USE SIGNAL ;
    SHAPE ABUTMENT ;
    PORT
      LAYER M4 ;
      RECT 0.000 177.024 0.024 177.048 ;
    END
  END addr_in_A[9]
  PIN addr_in_B[9]
    DIRECTION INPUT ;
    USE SIGNAL ;
    SHAPE ABUTMENT ;
    PORT
      LAYER M4 ;
      RECT 103.336 177.024 103.360 177.048 ;
    END
  END addr_in_B[9]
  PIN addr_in_A[10]
    DIRECTION INPUT ;
    USE SIGNAL ;
    SHAPE ABUTMENT ;
    PORT
      LAYER M4 ;
      RECT 0.000 177.888 0.024 177.912 ;
    END
  END addr_in_A[10]
  PIN addr_in_B[10]
    DIRECTION INPUT ;
    USE SIGNAL ;
    SHAPE ABUTMENT ;
    PORT
      LAYER M4 ;
      RECT 103.336 177.888 103.360 177.912 ;
    END
  END addr_in_B[10]
  PIN addr_in_A[11]
    DIRECTION INPUT ;
    USE SIGNAL ;
    SHAPE ABUTMENT ;
    PORT
      LAYER M4 ;
      RECT 0.000 178.752 0.024 178.776 ;
    END
  END addr_in_A[11]
  PIN addr_in_B[11]
    DIRECTION INPUT ;
    USE SIGNAL ;
    SHAPE ABUTMENT ;
    PORT
      LAYER M4 ;
      RECT 103.336 178.752 103.360 178.776 ;
    END
  END addr_in_B[11]
  PIN we_in_A
    DIRECTION INPUT ;
    USE SIGNAL ;
    SHAPE ABUTMENT ;
    PORT
      LAYER M4 ;
      RECT 0.000 180.720 0.024 180.744 ;
    END
  END we_in_A
  PIN we_in_B
    DIRECTION INPUT ;
    USE SIGNAL ;
    SHAPE ABUTMENT ;
    PORT
      LAYER M4 ;
      RECT 103.336 180.720 103.360 180.744 ;
    END
  END we_in_B
  PIN ce_in_A
    DIRECTION INPUT ;
    USE SIGNAL ;
    SHAPE ABUTMENT ;
    PORT
      LAYER M4 ;
      RECT 0.000 181.584 0.024 181.608 ;
    END
  END ce_in_A
  PIN clk_A
    DIRECTION INPUT ;
    USE SIGNAL ;
    SHAPE ABUTMENT ;
    PORT
      LAYER M4 ;
      RECT 0.000 182.448 0.024 182.472 ;
    END
  END clk_A
  PIN ce_in_B
    DIRECTION INPUT ;
    USE SIGNAL ;
    SHAPE ABUTMENT ;
    PORT
      LAYER M4 ;
      RECT 0.000 183.312 0.024 183.336 ;
    END
  END ce_in_B
  PIN clk_B
    DIRECTION INPUT ;
    USE SIGNAL ;
    SHAPE ABUTMENT ;
    PORT
      LAYER M4 ;
      RECT 0.000 184.176 0.024 184.200 ;
    END
  END clk_B
  PIN VSS
    DIRECTION INOUT ;
    USE GROUND ;
    PORT
      LAYER M4 ;
      RECT 0.048 0.000 103.312 0.096 ;
      RECT 0.048 0.768 103.312 0.864 ;
      RECT 0.048 1.536 103.312 1.632 ;
      RECT 0.048 2.304 103.312 2.400 ;
      RECT 0.048 3.072 103.312 3.168 ;
      RECT 0.048 3.840 103.312 3.936 ;
      RECT 0.048 4.608 103.312 4.704 ;
      RECT 0.048 5.376 103.312 5.472 ;
      RECT 0.048 6.144 103.312 6.240 ;
      RECT 0.048 6.912 103.312 7.008 ;
      RECT 0.048 7.680 103.312 7.776 ;
      RECT 0.048 8.448 103.312 8.544 ;
      RECT 0.048 9.216 103.312 9.312 ;
      RECT 0.048 9.984 103.312 10.080 ;
      RECT 0.048 10.752 103.312 10.848 ;
      RECT 0.048 11.520 103.312 11.616 ;
      RECT 0.048 12.288 103.312 12.384 ;
      RECT 0.048 13.056 103.312 13.152 ;
      RECT 0.048 13.824 103.312 13.920 ;
      RECT 0.048 14.592 103.312 14.688 ;
      RECT 0.048 15.360 103.312 15.456 ;
      RECT 0.048 16.128 103.312 16.224 ;
      RECT 0.048 16.896 103.312 16.992 ;
      RECT 0.048 17.664 103.312 17.760 ;
      RECT 0.048 18.432 103.312 18.528 ;
      RECT 0.048 19.200 103.312 19.296 ;
      RECT 0.048 19.968 103.312 20.064 ;
      RECT 0.048 20.736 103.312 20.832 ;
      RECT 0.048 21.504 103.312 21.600 ;
      RECT 0.048 22.272 103.312 22.368 ;
      RECT 0.048 23.040 103.312 23.136 ;
      RECT 0.048 23.808 103.312 23.904 ;
      RECT 0.048 24.576 103.312 24.672 ;
      RECT 0.048 25.344 103.312 25.440 ;
      RECT 0.048 26.112 103.312 26.208 ;
      RECT 0.048 26.880 103.312 26.976 ;
      RECT 0.048 27.648 103.312 27.744 ;
      RECT 0.048 28.416 103.312 28.512 ;
      RECT 0.048 29.184 103.312 29.280 ;
      RECT 0.048 29.952 103.312 30.048 ;
      RECT 0.048 30.720 103.312 30.816 ;
      RECT 0.048 31.488 103.312 31.584 ;
      RECT 0.048 32.256 103.312 32.352 ;
      RECT 0.048 33.024 103.312 33.120 ;
      RECT 0.048 33.792 103.312 33.888 ;
      RECT 0.048 34.560 103.312 34.656 ;
      RECT 0.048 35.328 103.312 35.424 ;
      RECT 0.048 36.096 103.312 36.192 ;
      RECT 0.048 36.864 103.312 36.960 ;
      RECT 0.048 37.632 103.312 37.728 ;
      RECT 0.048 38.400 103.312 38.496 ;
      RECT 0.048 39.168 103.312 39.264 ;
      RECT 0.048 39.936 103.312 40.032 ;
      RECT 0.048 40.704 103.312 40.800 ;
      RECT 0.048 41.472 103.312 41.568 ;
      RECT 0.048 42.240 103.312 42.336 ;
      RECT 0.048 43.008 103.312 43.104 ;
      RECT 0.048 43.776 103.312 43.872 ;
      RECT 0.048 44.544 103.312 44.640 ;
      RECT 0.048 45.312 103.312 45.408 ;
      RECT 0.048 46.080 103.312 46.176 ;
      RECT 0.048 46.848 103.312 46.944 ;
      RECT 0.048 47.616 103.312 47.712 ;
      RECT 0.048 48.384 103.312 48.480 ;
      RECT 0.048 49.152 103.312 49.248 ;
      RECT 0.048 49.920 103.312 50.016 ;
      RECT 0.048 50.688 103.312 50.784 ;
      RECT 0.048 51.456 103.312 51.552 ;
      RECT 0.048 52.224 103.312 52.320 ;
      RECT 0.048 52.992 103.312 53.088 ;
      RECT 0.048 53.760 103.312 53.856 ;
      RECT 0.048 54.528 103.312 54.624 ;
      RECT 0.048 55.296 103.312 55.392 ;
      RECT 0.048 56.064 103.312 56.160 ;
      RECT 0.048 56.832 103.312 56.928 ;
      RECT 0.048 57.600 103.312 57.696 ;
      RECT 0.048 58.368 103.312 58.464 ;
      RECT 0.048 59.136 103.312 59.232 ;
      RECT 0.048 59.904 103.312 60.000 ;
      RECT 0.048 60.672 103.312 60.768 ;
      RECT 0.048 61.440 103.312 61.536 ;
      RECT 0.048 62.208 103.312 62.304 ;
      RECT 0.048 62.976 103.312 63.072 ;
      RECT 0.048 63.744 103.312 63.840 ;
      RECT 0.048 64.512 103.312 64.608 ;
      RECT 0.048 65.280 103.312 65.376 ;
      RECT 0.048 66.048 103.312 66.144 ;
      RECT 0.048 66.816 103.312 66.912 ;
      RECT 0.048 67.584 103.312 67.680 ;
      RECT 0.048 68.352 103.312 68.448 ;
      RECT 0.048 69.120 103.312 69.216 ;
      RECT 0.048 69.888 103.312 69.984 ;
      RECT 0.048 70.656 103.312 70.752 ;
      RECT 0.048 71.424 103.312 71.520 ;
      RECT 0.048 72.192 103.312 72.288 ;
      RECT 0.048 72.960 103.312 73.056 ;
      RECT 0.048 73.728 103.312 73.824 ;
      RECT 0.048 74.496 103.312 74.592 ;
      RECT 0.048 75.264 103.312 75.360 ;
      RECT 0.048 76.032 103.312 76.128 ;
      RECT 0.048 76.800 103.312 76.896 ;
      RECT 0.048 77.568 103.312 77.664 ;
      RECT 0.048 78.336 103.312 78.432 ;
      RECT 0.048 79.104 103.312 79.200 ;
      RECT 0.048 79.872 103.312 79.968 ;
      RECT 0.048 80.640 103.312 80.736 ;
      RECT 0.048 81.408 103.312 81.504 ;
      RECT 0.048 82.176 103.312 82.272 ;
      RECT 0.048 82.944 103.312 83.040 ;
      RECT 0.048 83.712 103.312 83.808 ;
      RECT 0.048 84.480 103.312 84.576 ;
      RECT 0.048 85.248 103.312 85.344 ;
      RECT 0.048 86.016 103.312 86.112 ;
      RECT 0.048 86.784 103.312 86.880 ;
      RECT 0.048 87.552 103.312 87.648 ;
      RECT 0.048 88.320 103.312 88.416 ;
      RECT 0.048 89.088 103.312 89.184 ;
      RECT 0.048 89.856 103.312 89.952 ;
      RECT 0.048 90.624 103.312 90.720 ;
      RECT 0.048 91.392 103.312 91.488 ;
      RECT 0.048 92.160 103.312 92.256 ;
      RECT 0.048 92.928 103.312 93.024 ;
      RECT 0.048 93.696 103.312 93.792 ;
      RECT 0.048 94.464 103.312 94.560 ;
      RECT 0.048 95.232 103.312 95.328 ;
      RECT 0.048 96.000 103.312 96.096 ;
      RECT 0.048 96.768 103.312 96.864 ;
      RECT 0.048 97.536 103.312 97.632 ;
      RECT 0.048 98.304 103.312 98.400 ;
      RECT 0.048 99.072 103.312 99.168 ;
      RECT 0.048 99.840 103.312 99.936 ;
      RECT 0.048 100.608 103.312 100.704 ;
      RECT 0.048 101.376 103.312 101.472 ;
      RECT 0.048 102.144 103.312 102.240 ;
      RECT 0.048 102.912 103.312 103.008 ;
      RECT 0.048 103.680 103.312 103.776 ;
      RECT 0.048 104.448 103.312 104.544 ;
      RECT 0.048 105.216 103.312 105.312 ;
      RECT 0.048 105.984 103.312 106.080 ;
      RECT 0.048 106.752 103.312 106.848 ;
      RECT 0.048 107.520 103.312 107.616 ;
      RECT 0.048 108.288 103.312 108.384 ;
      RECT 0.048 109.056 103.312 109.152 ;
      RECT 0.048 109.824 103.312 109.920 ;
      RECT 0.048 110.592 103.312 110.688 ;
      RECT 0.048 111.360 103.312 111.456 ;
      RECT 0.048 112.128 103.312 112.224 ;
      RECT 0.048 112.896 103.312 112.992 ;
      RECT 0.048 113.664 103.312 113.760 ;
      RECT 0.048 114.432 103.312 114.528 ;
      RECT 0.048 115.200 103.312 115.296 ;
      RECT 0.048 115.968 103.312 116.064 ;
      RECT 0.048 116.736 103.312 116.832 ;
      RECT 0.048 117.504 103.312 117.600 ;
      RECT 0.048 118.272 103.312 118.368 ;
      RECT 0.048 119.040 103.312 119.136 ;
      RECT 0.048 119.808 103.312 119.904 ;
      RECT 0.048 120.576 103.312 120.672 ;
      RECT 0.048 121.344 103.312 121.440 ;
      RECT 0.048 122.112 103.312 122.208 ;
      RECT 0.048 122.880 103.312 122.976 ;
      RECT 0.048 123.648 103.312 123.744 ;
      RECT 0.048 124.416 103.312 124.512 ;
      RECT 0.048 125.184 103.312 125.280 ;
      RECT 0.048 125.952 103.312 126.048 ;
      RECT 0.048 126.720 103.312 126.816 ;
      RECT 0.048 127.488 103.312 127.584 ;
      RECT 0.048 128.256 103.312 128.352 ;
      RECT 0.048 129.024 103.312 129.120 ;
      RECT 0.048 129.792 103.312 129.888 ;
      RECT 0.048 130.560 103.312 130.656 ;
      RECT 0.048 131.328 103.312 131.424 ;
      RECT 0.048 132.096 103.312 132.192 ;
      RECT 0.048 132.864 103.312 132.960 ;
      RECT 0.048 133.632 103.312 133.728 ;
      RECT 0.048 134.400 103.312 134.496 ;
      RECT 0.048 135.168 103.312 135.264 ;
      RECT 0.048 135.936 103.312 136.032 ;
      RECT 0.048 136.704 103.312 136.800 ;
      RECT 0.048 137.472 103.312 137.568 ;
      RECT 0.048 138.240 103.312 138.336 ;
      RECT 0.048 139.008 103.312 139.104 ;
      RECT 0.048 139.776 103.312 139.872 ;
      RECT 0.048 140.544 103.312 140.640 ;
      RECT 0.048 141.312 103.312 141.408 ;
      RECT 0.048 142.080 103.312 142.176 ;
      RECT 0.048 142.848 103.312 142.944 ;
      RECT 0.048 143.616 103.312 143.712 ;
      RECT 0.048 144.384 103.312 144.480 ;
      RECT 0.048 145.152 103.312 145.248 ;
      RECT 0.048 145.920 103.312 146.016 ;
      RECT 0.048 146.688 103.312 146.784 ;
      RECT 0.048 147.456 103.312 147.552 ;
      RECT 0.048 148.224 103.312 148.320 ;
      RECT 0.048 148.992 103.312 149.088 ;
      RECT 0.048 149.760 103.312 149.856 ;
      RECT 0.048 150.528 103.312 150.624 ;
      RECT 0.048 151.296 103.312 151.392 ;
      RECT 0.048 152.064 103.312 152.160 ;
      RECT 0.048 152.832 103.312 152.928 ;
      RECT 0.048 153.600 103.312 153.696 ;
      RECT 0.048 154.368 103.312 154.464 ;
      RECT 0.048 155.136 103.312 155.232 ;
      RECT 0.048 155.904 103.312 156.000 ;
      RECT 0.048 156.672 103.312 156.768 ;
      RECT 0.048 157.440 103.312 157.536 ;
      RECT 0.048 158.208 103.312 158.304 ;
      RECT 0.048 158.976 103.312 159.072 ;
      RECT 0.048 159.744 103.312 159.840 ;
      RECT 0.048 160.512 103.312 160.608 ;
      RECT 0.048 161.280 103.312 161.376 ;
      RECT 0.048 162.048 103.312 162.144 ;
      RECT 0.048 162.816 103.312 162.912 ;
      RECT 0.048 163.584 103.312 163.680 ;
      RECT 0.048 164.352 103.312 164.448 ;
      RECT 0.048 165.120 103.312 165.216 ;
      RECT 0.048 165.888 103.312 165.984 ;
      RECT 0.048 166.656 103.312 166.752 ;
      RECT 0.048 167.424 103.312 167.520 ;
      RECT 0.048 168.192 103.312 168.288 ;
      RECT 0.048 168.960 103.312 169.056 ;
      RECT 0.048 169.728 103.312 169.824 ;
      RECT 0.048 170.496 103.312 170.592 ;
      RECT 0.048 171.264 103.312 171.360 ;
      RECT 0.048 172.032 103.312 172.128 ;
      RECT 0.048 172.800 103.312 172.896 ;
      RECT 0.048 173.568 103.312 173.664 ;
      RECT 0.048 174.336 103.312 174.432 ;
      RECT 0.048 175.104 103.312 175.200 ;
      RECT 0.048 175.872 103.312 175.968 ;
      RECT 0.048 176.640 103.312 176.736 ;
      RECT 0.048 177.408 103.312 177.504 ;
      RECT 0.048 178.176 103.312 178.272 ;
      RECT 0.048 178.944 103.312 179.040 ;
      RECT 0.048 179.712 103.312 179.808 ;
      RECT 0.048 180.480 103.312 180.576 ;
      RECT 0.048 181.248 103.312 181.344 ;
      RECT 0.048 182.016 103.312 182.112 ;
      RECT 0.048 182.784 103.312 182.880 ;
    END
  END VSS
  PIN VDD
    DIRECTION INOUT ;
    USE POWER ;
    PORT
      LAYER M4 ;
      RECT 0.048 0.384 103.312 0.480 ;
      RECT 0.048 1.152 103.312 1.248 ;
      RECT 0.048 1.920 103.312 2.016 ;
      RECT 0.048 2.688 103.312 2.784 ;
      RECT 0.048 3.456 103.312 3.552 ;
      RECT 0.048 4.224 103.312 4.320 ;
      RECT 0.048 4.992 103.312 5.088 ;
      RECT 0.048 5.760 103.312 5.856 ;
      RECT 0.048 6.528 103.312 6.624 ;
      RECT 0.048 7.296 103.312 7.392 ;
      RECT 0.048 8.064 103.312 8.160 ;
      RECT 0.048 8.832 103.312 8.928 ;
      RECT 0.048 9.600 103.312 9.696 ;
      RECT 0.048 10.368 103.312 10.464 ;
      RECT 0.048 11.136 103.312 11.232 ;
      RECT 0.048 11.904 103.312 12.000 ;
      RECT 0.048 12.672 103.312 12.768 ;
      RECT 0.048 13.440 103.312 13.536 ;
      RECT 0.048 14.208 103.312 14.304 ;
      RECT 0.048 14.976 103.312 15.072 ;
      RECT 0.048 15.744 103.312 15.840 ;
      RECT 0.048 16.512 103.312 16.608 ;
      RECT 0.048 17.280 103.312 17.376 ;
      RECT 0.048 18.048 103.312 18.144 ;
      RECT 0.048 18.816 103.312 18.912 ;
      RECT 0.048 19.584 103.312 19.680 ;
      RECT 0.048 20.352 103.312 20.448 ;
      RECT 0.048 21.120 103.312 21.216 ;
      RECT 0.048 21.888 103.312 21.984 ;
      RECT 0.048 22.656 103.312 22.752 ;
      RECT 0.048 23.424 103.312 23.520 ;
      RECT 0.048 24.192 103.312 24.288 ;
      RECT 0.048 24.960 103.312 25.056 ;
      RECT 0.048 25.728 103.312 25.824 ;
      RECT 0.048 26.496 103.312 26.592 ;
      RECT 0.048 27.264 103.312 27.360 ;
      RECT 0.048 28.032 103.312 28.128 ;
      RECT 0.048 28.800 103.312 28.896 ;
      RECT 0.048 29.568 103.312 29.664 ;
      RECT 0.048 30.336 103.312 30.432 ;
      RECT 0.048 31.104 103.312 31.200 ;
      RECT 0.048 31.872 103.312 31.968 ;
      RECT 0.048 32.640 103.312 32.736 ;
      RECT 0.048 33.408 103.312 33.504 ;
      RECT 0.048 34.176 103.312 34.272 ;
      RECT 0.048 34.944 103.312 35.040 ;
      RECT 0.048 35.712 103.312 35.808 ;
      RECT 0.048 36.480 103.312 36.576 ;
      RECT 0.048 37.248 103.312 37.344 ;
      RECT 0.048 38.016 103.312 38.112 ;
      RECT 0.048 38.784 103.312 38.880 ;
      RECT 0.048 39.552 103.312 39.648 ;
      RECT 0.048 40.320 103.312 40.416 ;
      RECT 0.048 41.088 103.312 41.184 ;
      RECT 0.048 41.856 103.312 41.952 ;
      RECT 0.048 42.624 103.312 42.720 ;
      RECT 0.048 43.392 103.312 43.488 ;
      RECT 0.048 44.160 103.312 44.256 ;
      RECT 0.048 44.928 103.312 45.024 ;
      RECT 0.048 45.696 103.312 45.792 ;
      RECT 0.048 46.464 103.312 46.560 ;
      RECT 0.048 47.232 103.312 47.328 ;
      RECT 0.048 48.000 103.312 48.096 ;
      RECT 0.048 48.768 103.312 48.864 ;
      RECT 0.048 49.536 103.312 49.632 ;
      RECT 0.048 50.304 103.312 50.400 ;
      RECT 0.048 51.072 103.312 51.168 ;
      RECT 0.048 51.840 103.312 51.936 ;
      RECT 0.048 52.608 103.312 52.704 ;
      RECT 0.048 53.376 103.312 53.472 ;
      RECT 0.048 54.144 103.312 54.240 ;
      RECT 0.048 54.912 103.312 55.008 ;
      RECT 0.048 55.680 103.312 55.776 ;
      RECT 0.048 56.448 103.312 56.544 ;
      RECT 0.048 57.216 103.312 57.312 ;
      RECT 0.048 57.984 103.312 58.080 ;
      RECT 0.048 58.752 103.312 58.848 ;
      RECT 0.048 59.520 103.312 59.616 ;
      RECT 0.048 60.288 103.312 60.384 ;
      RECT 0.048 61.056 103.312 61.152 ;
      RECT 0.048 61.824 103.312 61.920 ;
      RECT 0.048 62.592 103.312 62.688 ;
      RECT 0.048 63.360 103.312 63.456 ;
      RECT 0.048 64.128 103.312 64.224 ;
      RECT 0.048 64.896 103.312 64.992 ;
      RECT 0.048 65.664 103.312 65.760 ;
      RECT 0.048 66.432 103.312 66.528 ;
      RECT 0.048 67.200 103.312 67.296 ;
      RECT 0.048 67.968 103.312 68.064 ;
      RECT 0.048 68.736 103.312 68.832 ;
      RECT 0.048 69.504 103.312 69.600 ;
      RECT 0.048 70.272 103.312 70.368 ;
      RECT 0.048 71.040 103.312 71.136 ;
      RECT 0.048 71.808 103.312 71.904 ;
      RECT 0.048 72.576 103.312 72.672 ;
      RECT 0.048 73.344 103.312 73.440 ;
      RECT 0.048 74.112 103.312 74.208 ;
      RECT 0.048 74.880 103.312 74.976 ;
      RECT 0.048 75.648 103.312 75.744 ;
      RECT 0.048 76.416 103.312 76.512 ;
      RECT 0.048 77.184 103.312 77.280 ;
      RECT 0.048 77.952 103.312 78.048 ;
      RECT 0.048 78.720 103.312 78.816 ;
      RECT 0.048 79.488 103.312 79.584 ;
      RECT 0.048 80.256 103.312 80.352 ;
      RECT 0.048 81.024 103.312 81.120 ;
      RECT 0.048 81.792 103.312 81.888 ;
      RECT 0.048 82.560 103.312 82.656 ;
      RECT 0.048 83.328 103.312 83.424 ;
      RECT 0.048 84.096 103.312 84.192 ;
      RECT 0.048 84.864 103.312 84.960 ;
      RECT 0.048 85.632 103.312 85.728 ;
      RECT 0.048 86.400 103.312 86.496 ;
      RECT 0.048 87.168 103.312 87.264 ;
      RECT 0.048 87.936 103.312 88.032 ;
      RECT 0.048 88.704 103.312 88.800 ;
      RECT 0.048 89.472 103.312 89.568 ;
      RECT 0.048 90.240 103.312 90.336 ;
      RECT 0.048 91.008 103.312 91.104 ;
      RECT 0.048 91.776 103.312 91.872 ;
      RECT 0.048 92.544 103.312 92.640 ;
      RECT 0.048 93.312 103.312 93.408 ;
      RECT 0.048 94.080 103.312 94.176 ;
      RECT 0.048 94.848 103.312 94.944 ;
      RECT 0.048 95.616 103.312 95.712 ;
      RECT 0.048 96.384 103.312 96.480 ;
      RECT 0.048 97.152 103.312 97.248 ;
      RECT 0.048 97.920 103.312 98.016 ;
      RECT 0.048 98.688 103.312 98.784 ;
      RECT 0.048 99.456 103.312 99.552 ;
      RECT 0.048 100.224 103.312 100.320 ;
      RECT 0.048 100.992 103.312 101.088 ;
      RECT 0.048 101.760 103.312 101.856 ;
      RECT 0.048 102.528 103.312 102.624 ;
      RECT 0.048 103.296 103.312 103.392 ;
      RECT 0.048 104.064 103.312 104.160 ;
      RECT 0.048 104.832 103.312 104.928 ;
      RECT 0.048 105.600 103.312 105.696 ;
      RECT 0.048 106.368 103.312 106.464 ;
      RECT 0.048 107.136 103.312 107.232 ;
      RECT 0.048 107.904 103.312 108.000 ;
      RECT 0.048 108.672 103.312 108.768 ;
      RECT 0.048 109.440 103.312 109.536 ;
      RECT 0.048 110.208 103.312 110.304 ;
      RECT 0.048 110.976 103.312 111.072 ;
      RECT 0.048 111.744 103.312 111.840 ;
      RECT 0.048 112.512 103.312 112.608 ;
      RECT 0.048 113.280 103.312 113.376 ;
      RECT 0.048 114.048 103.312 114.144 ;
      RECT 0.048 114.816 103.312 114.912 ;
      RECT 0.048 115.584 103.312 115.680 ;
      RECT 0.048 116.352 103.312 116.448 ;
      RECT 0.048 117.120 103.312 117.216 ;
      RECT 0.048 117.888 103.312 117.984 ;
      RECT 0.048 118.656 103.312 118.752 ;
      RECT 0.048 119.424 103.312 119.520 ;
      RECT 0.048 120.192 103.312 120.288 ;
      RECT 0.048 120.960 103.312 121.056 ;
      RECT 0.048 121.728 103.312 121.824 ;
      RECT 0.048 122.496 103.312 122.592 ;
      RECT 0.048 123.264 103.312 123.360 ;
      RECT 0.048 124.032 103.312 124.128 ;
      RECT 0.048 124.800 103.312 124.896 ;
      RECT 0.048 125.568 103.312 125.664 ;
      RECT 0.048 126.336 103.312 126.432 ;
      RECT 0.048 127.104 103.312 127.200 ;
      RECT 0.048 127.872 103.312 127.968 ;
      RECT 0.048 128.640 103.312 128.736 ;
      RECT 0.048 129.408 103.312 129.504 ;
      RECT 0.048 130.176 103.312 130.272 ;
      RECT 0.048 130.944 103.312 131.040 ;
      RECT 0.048 131.712 103.312 131.808 ;
      RECT 0.048 132.480 103.312 132.576 ;
      RECT 0.048 133.248 103.312 133.344 ;
      RECT 0.048 134.016 103.312 134.112 ;
      RECT 0.048 134.784 103.312 134.880 ;
      RECT 0.048 135.552 103.312 135.648 ;
      RECT 0.048 136.320 103.312 136.416 ;
      RECT 0.048 137.088 103.312 137.184 ;
      RECT 0.048 137.856 103.312 137.952 ;
      RECT 0.048 138.624 103.312 138.720 ;
      RECT 0.048 139.392 103.312 139.488 ;
      RECT 0.048 140.160 103.312 140.256 ;
      RECT 0.048 140.928 103.312 141.024 ;
      RECT 0.048 141.696 103.312 141.792 ;
      RECT 0.048 142.464 103.312 142.560 ;
      RECT 0.048 143.232 103.312 143.328 ;
      RECT 0.048 144.000 103.312 144.096 ;
      RECT 0.048 144.768 103.312 144.864 ;
      RECT 0.048 145.536 103.312 145.632 ;
      RECT 0.048 146.304 103.312 146.400 ;
      RECT 0.048 147.072 103.312 147.168 ;
      RECT 0.048 147.840 103.312 147.936 ;
      RECT 0.048 148.608 103.312 148.704 ;
      RECT 0.048 149.376 103.312 149.472 ;
      RECT 0.048 150.144 103.312 150.240 ;
      RECT 0.048 150.912 103.312 151.008 ;
      RECT 0.048 151.680 103.312 151.776 ;
      RECT 0.048 152.448 103.312 152.544 ;
      RECT 0.048 153.216 103.312 153.312 ;
      RECT 0.048 153.984 103.312 154.080 ;
      RECT 0.048 154.752 103.312 154.848 ;
      RECT 0.048 155.520 103.312 155.616 ;
      RECT 0.048 156.288 103.312 156.384 ;
      RECT 0.048 157.056 103.312 157.152 ;
      RECT 0.048 157.824 103.312 157.920 ;
      RECT 0.048 158.592 103.312 158.688 ;
      RECT 0.048 159.360 103.312 159.456 ;
      RECT 0.048 160.128 103.312 160.224 ;
      RECT 0.048 160.896 103.312 160.992 ;
      RECT 0.048 161.664 103.312 161.760 ;
      RECT 0.048 162.432 103.312 162.528 ;
      RECT 0.048 163.200 103.312 163.296 ;
      RECT 0.048 163.968 103.312 164.064 ;
      RECT 0.048 164.736 103.312 164.832 ;
      RECT 0.048 165.504 103.312 165.600 ;
      RECT 0.048 166.272 103.312 166.368 ;
      RECT 0.048 167.040 103.312 167.136 ;
      RECT 0.048 167.808 103.312 167.904 ;
      RECT 0.048 168.576 103.312 168.672 ;
      RECT 0.048 169.344 103.312 169.440 ;
      RECT 0.048 170.112 103.312 170.208 ;
      RECT 0.048 170.880 103.312 170.976 ;
      RECT 0.048 171.648 103.312 171.744 ;
      RECT 0.048 172.416 103.312 172.512 ;
      RECT 0.048 173.184 103.312 173.280 ;
      RECT 0.048 173.952 103.312 174.048 ;
      RECT 0.048 174.720 103.312 174.816 ;
      RECT 0.048 175.488 103.312 175.584 ;
      RECT 0.048 176.256 103.312 176.352 ;
      RECT 0.048 177.024 103.312 177.120 ;
      RECT 0.048 177.792 103.312 177.888 ;
      RECT 0.048 178.560 103.312 178.656 ;
      RECT 0.048 179.328 103.312 179.424 ;
      RECT 0.048 180.096 103.312 180.192 ;
      RECT 0.048 180.864 103.312 180.960 ;
      RECT 0.048 181.632 103.312 181.728 ;
      RECT 0.048 182.400 103.312 182.496 ;
      RECT 0.048 183.168 103.312 183.264 ;
    END
  END VDD
  OBS
    LAYER M1 ;
    RECT 0 0 103.360 183.400 ;
    LAYER M2 ;
    RECT 0 0 103.360 183.400 ;
    LAYER M3 ;
    RECT 0 0 103.360 183.400 ;
    LAYER M4 ;
    RECT 0 0 103.360 183.400 ;
  END
END fakeram7_tdp_4096x64

END LIBRARY
